VERSION 5.7 ;
  NOWIREEXTENSIONATPIN ON ;
  DIVIDERCHAR "/" ;
  BUSBITCHARS "[]" ;
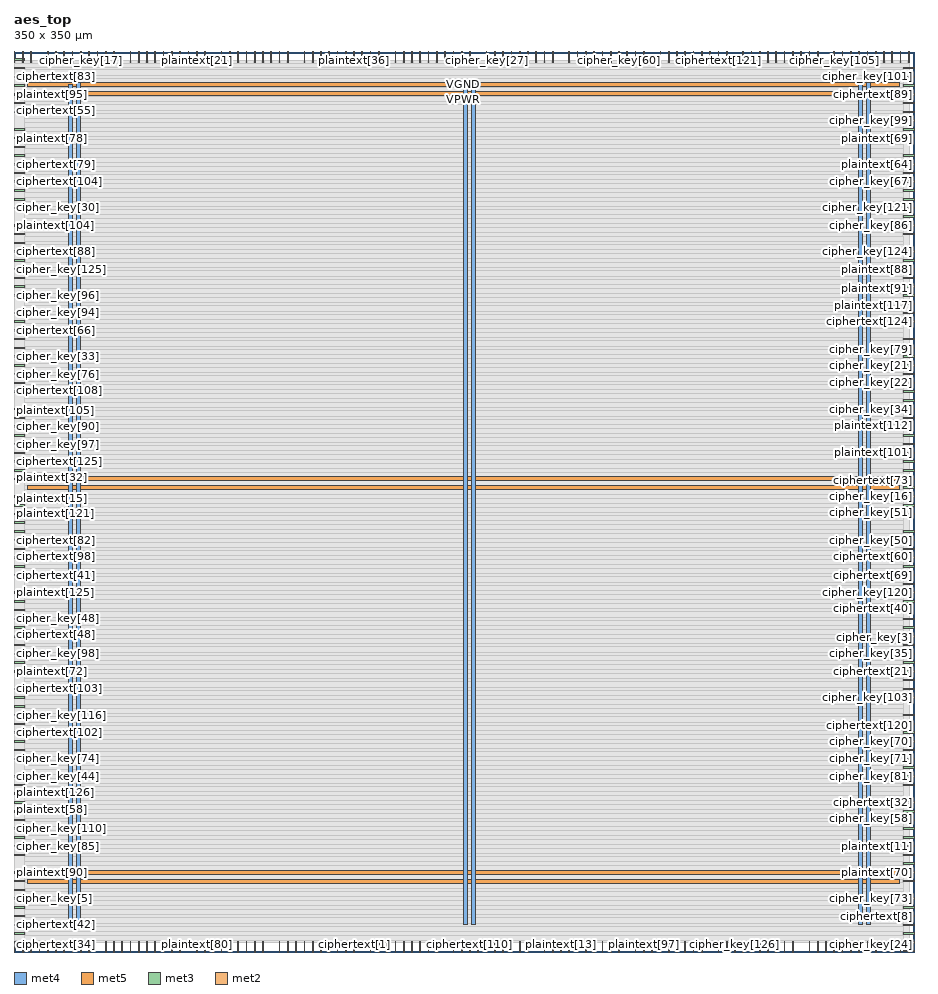
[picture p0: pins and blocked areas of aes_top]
MACRO aes_top
  CLASS BLOCK ;
  FOREIGN aes_top ;
  ORIGIN 0.000 0.000 ;
  SIZE 350.000 BY 350.000 ;
  PIN VGND
    DIRECTION INOUT ;
    USE GROUND ;
    PORT
      LAYER met4 ;
        RECT 24.340 10.640 25.940 337.990 ;
    END
    PORT
      LAYER met4 ;
        RECT 177.940 10.640 179.540 337.990 ;
    END
    PORT
      LAYER met4 ;
        RECT 331.540 10.640 333.140 337.990 ;
    END
    PORT
      LAYER met5 ;
        RECT 5.280 30.030 344.320 31.630 ;
    END
    PORT
      LAYER met5 ;
        RECT 5.280 183.210 344.320 184.810 ;
    END
    PORT
      LAYER met5 ;
        RECT 5.280 336.390 344.320 337.990 ;
    END
  END VGND
  PIN VPWR
    DIRECTION INOUT ;
    USE POWER ;
    PORT
      LAYER met4 ;
        RECT 21.040 10.640 22.640 337.520 ;
    END
    PORT
      LAYER met4 ;
        RECT 174.640 10.640 176.240 337.520 ;
    END
    PORT
      LAYER met4 ;
        RECT 328.240 10.640 329.840 337.520 ;
    END
    PORT
      LAYER met5 ;
        RECT 5.280 26.730 344.320 28.330 ;
    END
    PORT
      LAYER met5 ;
        RECT 5.280 179.910 344.320 181.510 ;
    END
    PORT
      LAYER met5 ;
        RECT 5.280 333.090 344.320 334.690 ;
    END
  END VPWR
  PIN cipher_key[0]
    DIRECTION INPUT ;
    USE SIGNAL ;
    PORT
      LAYER met3 ;
        RECT 346.000 34.040 350.000 34.640 ;
    END
  END cipher_key[0]
  PIN cipher_key[100]
    DIRECTION INPUT ;
    USE SIGNAL ;
    PORT
      LAYER met2 ;
        RECT 58.050 346.000 58.330 350.000 ;
    END
  END cipher_key[100]
  PIN cipher_key[101]
    DIRECTION INPUT ;
    USE SIGNAL ;
    PORT
      LAYER met3 ;
        RECT 346.000 340.040 350.000 340.640 ;
    END
  END cipher_key[101]
  PIN cipher_key[102]
    DIRECTION INPUT ;
    USE SIGNAL ;
    PORT
      LAYER met2 ;
        RECT 264.130 0.000 264.410 4.000 ;
    END
  END cipher_key[102]
  PIN cipher_key[103]
    DIRECTION INPUT ;
    USE SIGNAL ;
    PORT
      LAYER met3 ;
        RECT 346.000 98.640 350.000 99.240 ;
    END
  END cipher_key[103]
  PIN cipher_key[104]
    DIRECTION INPUT ;
    USE SIGNAL ;
    PORT
      LAYER met3 ;
        RECT 346.000 27.240 350.000 27.840 ;
    END
  END cipher_key[104]
  PIN cipher_key[105]
    DIRECTION INPUT ;
    USE SIGNAL ;
    PORT
      LAYER met2 ;
        RECT 318.870 346.000 319.150 350.000 ;
    END
  END cipher_key[105]
  PIN cipher_key[106]
    DIRECTION INPUT ;
    USE SIGNAL ;
    PORT
      LAYER met2 ;
        RECT 138.550 346.000 138.830 350.000 ;
    END
  END cipher_key[106]
  PIN cipher_key[107]
    DIRECTION INPUT ;
    USE SIGNAL ;
    PORT
      LAYER met3 ;
        RECT 0.000 292.440 4.000 293.040 ;
    END
  END cipher_key[107]
  PIN cipher_key[108]
    DIRECTION INPUT ;
    USE SIGNAL ;
    PORT
      LAYER met2 ;
        RECT 116.010 0.000 116.290 4.000 ;
    END
  END cipher_key[108]
  PIN cipher_key[109]
    DIRECTION INPUT ;
    USE SIGNAL ;
    PORT
      LAYER met2 ;
        RECT 241.590 346.000 241.870 350.000 ;
    END
  END cipher_key[109]
  PIN cipher_key[10]
    DIRECTION INPUT ;
    USE SIGNAL ;
    PORT
      LAYER met3 ;
        RECT 0.000 112.240 4.000 112.840 ;
    END
  END cipher_key[10]
  PIN cipher_key[110]
    DIRECTION INPUT ;
    USE SIGNAL ;
    PORT
      LAYER met3 ;
        RECT 0.000 47.640 4.000 48.240 ;
    END
  END cipher_key[110]
  PIN cipher_key[111]
    DIRECTION INPUT ;
    USE SIGNAL ;
    PORT
      LAYER met2 ;
        RECT 148.210 0.000 148.490 4.000 ;
    END
  END cipher_key[111]
  PIN cipher_key[112]
    DIRECTION INPUT ;
    USE SIGNAL ;
    PORT
      LAYER met3 ;
        RECT 0.000 88.440 4.000 89.040 ;
    END
  END cipher_key[112]
  PIN cipher_key[113]
    DIRECTION INPUT ;
    USE SIGNAL ;
    PORT
      LAYER met3 ;
        RECT 0.000 17.040 4.000 17.640 ;
    END
  END cipher_key[113]
  PIN cipher_key[114]
    DIRECTION INPUT ;
    USE SIGNAL ;
    PORT
      LAYER met3 ;
        RECT 0.000 346.840 4.000 347.440 ;
    END
  END cipher_key[114]
  PIN cipher_key[115]
    DIRECTION INPUT ;
    USE SIGNAL ;
    PORT
      LAYER met2 ;
        RECT 328.530 346.000 328.810 350.000 ;
    END
  END cipher_key[115]
  PIN cipher_key[116]
    DIRECTION INPUT ;
    USE SIGNAL ;
    PORT
      LAYER met3 ;
        RECT 0.000 91.840 4.000 92.440 ;
    END
  END cipher_key[116]
  PIN cipher_key[117]
    DIRECTION INPUT ;
    USE SIGNAL ;
    PORT
      LAYER met2 ;
        RECT 154.650 346.000 154.930 350.000 ;
    END
  END cipher_key[117]
  PIN cipher_key[118]
    DIRECTION INPUT ;
    USE SIGNAL ;
    PORT
      LAYER met3 ;
        RECT 0.000 183.640 4.000 184.240 ;
    END
  END cipher_key[118]
  PIN cipher_key[119]
    DIRECTION INPUT ;
    USE SIGNAL ;
    PORT
      LAYER met3 ;
        RECT 346.000 302.640 350.000 303.240 ;
    END
  END cipher_key[119]
  PIN cipher_key[11]
    DIRECTION INPUT ;
    USE SIGNAL ;
    PORT
      LAYER met2 ;
        RECT 148.210 346.000 148.490 350.000 ;
    END
  END cipher_key[11]
  PIN cipher_key[120]
    DIRECTION INPUT ;
    USE SIGNAL ;
    PORT
      LAYER met3 ;
        RECT 346.000 139.440 350.000 140.040 ;
    END
  END cipher_key[120]
  PIN cipher_key[121]
    DIRECTION INPUT ;
    USE SIGNAL ;
    PORT
      LAYER met3 ;
        RECT 346.000 289.040 350.000 289.640 ;
    END
  END cipher_key[121]
  PIN cipher_key[122]
    DIRECTION INPUT ;
    USE SIGNAL ;
    PORT
      LAYER met2 ;
        RECT 228.710 0.000 228.990 4.000 ;
    END
  END cipher_key[122]
  PIN cipher_key[123]
    DIRECTION INPUT ;
    USE SIGNAL ;
    PORT
      LAYER met3 ;
        RECT 346.000 71.440 350.000 72.040 ;
    END
  END cipher_key[123]
  PIN cipher_key[124]
    DIRECTION INPUT ;
    USE SIGNAL ;
    PORT
      LAYER met3 ;
        RECT 346.000 272.040 350.000 272.640 ;
    END
  END cipher_key[124]
  PIN cipher_key[125]
    DIRECTION INPUT ;
    USE SIGNAL ;
    PORT
      LAYER met3 ;
        RECT 0.000 265.240 4.000 265.840 ;
    END
  END cipher_key[125]
  PIN cipher_key[126]
    DIRECTION INPUT ;
    USE SIGNAL ;
    PORT
      LAYER met2 ;
        RECT 280.230 0.000 280.510 4.000 ;
    END
  END cipher_key[126]
  PIN cipher_key[127]
    DIRECTION INPUT ;
    USE SIGNAL ;
    PORT
      LAYER met3 ;
        RECT 0.000 261.840 4.000 262.440 ;
    END
  END cipher_key[127]
  PIN cipher_key[12]
    DIRECTION INPUT ;
    USE SIGNAL ;
    PORT
      LAYER met2 ;
        RECT 77.370 0.000 77.650 4.000 ;
    END
  END cipher_key[12]
  PIN cipher_key[13]
    DIRECTION INPUT ;
    USE SIGNAL ;
    PORT
      LAYER met2 ;
        RECT 6.530 346.000 6.810 350.000 ;
    END
  END cipher_key[13]
  PIN cipher_key[14]
    DIRECTION INPUT ;
    USE SIGNAL ;
    PORT
      LAYER met2 ;
        RECT 264.130 346.000 264.410 350.000 ;
    END
  END cipher_key[14]
  PIN cipher_key[15]
    DIRECTION INPUT ;
    USE SIGNAL ;
    PORT
      LAYER met2 ;
        RECT 328.530 0.000 328.810 4.000 ;
    END
  END cipher_key[15]
  PIN cipher_key[16]
    DIRECTION INPUT ;
    USE SIGNAL ;
    PORT
      LAYER met3 ;
        RECT 346.000 176.840 350.000 177.440 ;
    END
  END cipher_key[16]
  PIN cipher_key[17]
    DIRECTION INPUT ;
    USE SIGNAL ;
    PORT
      LAYER met2 ;
        RECT 25.850 346.000 26.130 350.000 ;
    END
  END cipher_key[17]
  PIN cipher_key[18]
    DIRECTION INPUT ;
    USE SIGNAL ;
    PORT
      LAYER met2 ;
        RECT 22.630 346.000 22.910 350.000 ;
    END
  END cipher_key[18]
  PIN cipher_key[19]
    DIRECTION INPUT ;
    USE SIGNAL ;
    PORT
      LAYER met2 ;
        RECT 289.890 346.000 290.170 350.000 ;
    END
  END cipher_key[19]
  PIN cipher_key[1]
    DIRECTION INPUT ;
    USE SIGNAL ;
    PORT
      LAYER met3 ;
        RECT 0.000 343.440 4.000 344.040 ;
    END
  END cipher_key[1]
  PIN cipher_key[20]
    DIRECTION INPUT ;
    USE SIGNAL ;
    PORT
      LAYER met3 ;
        RECT 0.000 234.640 4.000 235.240 ;
    END
  END cipher_key[20]
  PIN cipher_key[21]
    DIRECTION INPUT ;
    USE SIGNAL ;
    PORT
      LAYER met3 ;
        RECT 346.000 227.840 350.000 228.440 ;
    END
  END cipher_key[21]
  PIN cipher_key[22]
    DIRECTION INPUT ;
    USE SIGNAL ;
    PORT
      LAYER met3 ;
        RECT 346.000 221.040 350.000 221.640 ;
    END
  END cipher_key[22]
  PIN cipher_key[23]
    DIRECTION INPUT ;
    USE SIGNAL ;
    PORT
      LAYER met3 ;
        RECT 346.000 285.640 350.000 286.240 ;
    END
  END cipher_key[23]
  PIN cipher_key[24]
    DIRECTION INPUT ;
    USE SIGNAL ;
    PORT
      LAYER met2 ;
        RECT 341.410 0.000 341.690 4.000 ;
    END
  END cipher_key[24]
  PIN cipher_key[25]
    DIRECTION INPUT ;
    USE SIGNAL ;
    PORT
      LAYER met2 ;
        RECT 93.470 346.000 93.750 350.000 ;
    END
  END cipher_key[25]
  PIN cipher_key[26]
    DIRECTION INPUT ;
    USE SIGNAL ;
    PORT
      LAYER met2 ;
        RECT 141.770 0.000 142.050 4.000 ;
    END
  END cipher_key[26]
  PIN cipher_key[27]
    DIRECTION INPUT ;
    USE SIGNAL ;
    PORT
      LAYER met2 ;
        RECT 183.630 346.000 183.910 350.000 ;
    END
  END cipher_key[27]
  PIN cipher_key[28]
    DIRECTION INPUT ;
    USE SIGNAL ;
    PORT
      LAYER met3 ;
        RECT 0.000 268.640 4.000 269.240 ;
    END
  END cipher_key[28]
  PIN cipher_key[29]
    DIRECTION INPUT ;
    USE SIGNAL ;
    PORT
      LAYER met2 ;
        RECT 29.070 0.000 29.350 4.000 ;
    END
  END cipher_key[29]
  PIN cipher_key[2]
    DIRECTION INPUT ;
    USE SIGNAL ;
    PORT
      LAYER met2 ;
        RECT 241.590 0.000 241.870 4.000 ;
    END
  END cipher_key[2]
  PIN cipher_key[30]
    DIRECTION INPUT ;
    USE SIGNAL ;
    PORT
      LAYER met3 ;
        RECT 0.000 289.040 4.000 289.640 ;
    END
  END cipher_key[30]
  PIN cipher_key[31]
    DIRECTION INPUT ;
    USE SIGNAL ;
    PORT
      LAYER met2 ;
        RECT 347.850 346.000 348.130 350.000 ;
    END
  END cipher_key[31]
  PIN cipher_key[32]
    DIRECTION INPUT ;
    USE SIGNAL ;
    PORT
      LAYER met2 ;
        RECT 64.490 346.000 64.770 350.000 ;
    END
  END cipher_key[32]
  PIN cipher_key[33]
    DIRECTION INPUT ;
    USE SIGNAL ;
    PORT
      LAYER met3 ;
        RECT 0.000 231.240 4.000 231.840 ;
    END
  END cipher_key[33]
  PIN cipher_key[34]
    DIRECTION INPUT ;
    USE SIGNAL ;
    PORT
      LAYER met3 ;
        RECT 346.000 210.840 350.000 211.440 ;
    END
  END cipher_key[34]
  PIN cipher_key[35]
    DIRECTION INPUT ;
    USE SIGNAL ;
    PORT
      LAYER met3 ;
        RECT 346.000 115.640 350.000 116.240 ;
    END
  END cipher_key[35]
  PIN cipher_key[36]
    DIRECTION INPUT ;
    USE SIGNAL ;
    PORT
      LAYER met2 ;
        RECT 109.570 0.000 109.850 4.000 ;
    END
  END cipher_key[36]
  PIN cipher_key[37]
    DIRECTION INPUT ;
    USE SIGNAL ;
    PORT
      LAYER met2 ;
        RECT 222.270 0.000 222.550 4.000 ;
    END
  END cipher_key[37]
  PIN cipher_key[38]
    DIRECTION INPUT ;
    USE SIGNAL ;
    PORT
      LAYER met3 ;
        RECT 0.000 149.640 4.000 150.240 ;
    END
  END cipher_key[38]
  PIN cipher_key[39]
    DIRECTION INPUT ;
    USE SIGNAL ;
    PORT
      LAYER met2 ;
        RECT 338.190 346.000 338.470 350.000 ;
    END
  END cipher_key[39]
  PIN cipher_key[3]
    DIRECTION INPUT ;
    USE SIGNAL ;
    PORT
      LAYER met3 ;
        RECT 346.000 119.040 350.000 119.640 ;
    END
  END cipher_key[3]
  PIN cipher_key[40]
    DIRECTION INPUT ;
    USE SIGNAL ;
    PORT
      LAYER met2 ;
        RECT 296.330 0.000 296.610 4.000 ;
    END
  END cipher_key[40]
  PIN cipher_key[41]
    DIRECTION INPUT ;
    USE SIGNAL ;
    PORT
      LAYER met2 ;
        RECT 299.550 0.000 299.830 4.000 ;
    END
  END cipher_key[41]
  PIN cipher_key[42]
    DIRECTION INPUT ;
    USE SIGNAL ;
    PORT
      LAYER met3 ;
        RECT 346.000 326.440 350.000 327.040 ;
    END
  END cipher_key[42]
  PIN cipher_key[43]
    DIRECTION INPUT ;
    USE SIGNAL ;
    PORT
      LAYER met2 ;
        RECT 125.670 346.000 125.950 350.000 ;
    END
  END cipher_key[43]
  PIN cipher_key[44]
    DIRECTION INPUT ;
    USE SIGNAL ;
    PORT
      LAYER met3 ;
        RECT 0.000 68.040 4.000 68.640 ;
    END
  END cipher_key[44]
  PIN cipher_key[45]
    DIRECTION INPUT ;
    USE SIGNAL ;
    PORT
      LAYER met2 ;
        RECT 283.450 346.000 283.730 350.000 ;
    END
  END cipher_key[45]
  PIN cipher_key[46]
    DIRECTION INPUT ;
    USE SIGNAL ;
    PORT
      LAYER met3 ;
        RECT 346.000 6.840 350.000 7.440 ;
    END
  END cipher_key[46]
  PIN cipher_key[47]
    DIRECTION INPUT ;
    USE SIGNAL ;
    PORT
      LAYER met3 ;
        RECT 0.000 336.640 4.000 337.240 ;
    END
  END cipher_key[47]
  PIN cipher_key[48]
    DIRECTION INPUT ;
    USE SIGNAL ;
    PORT
      LAYER met3 ;
        RECT 0.000 129.240 4.000 129.840 ;
    END
  END cipher_key[48]
  PIN cipher_key[49]
    DIRECTION INPUT ;
    USE SIGNAL ;
    PORT
      LAYER met2 ;
        RECT 173.970 346.000 174.250 350.000 ;
    END
  END cipher_key[49]
  PIN cipher_key[4]
    DIRECTION INPUT ;
    USE SIGNAL ;
    PORT
      LAYER met3 ;
        RECT 346.000 278.840 350.000 279.440 ;
    END
  END cipher_key[4]
  PIN cipher_key[50]
    DIRECTION INPUT ;
    USE SIGNAL ;
    PORT
      LAYER met3 ;
        RECT 346.000 159.840 350.000 160.440 ;
    END
  END cipher_key[50]
  PIN cipher_key[51]
    DIRECTION INPUT ;
    USE SIGNAL ;
    PORT
      LAYER met3 ;
        RECT 346.000 173.440 350.000 174.040 ;
    END
  END cipher_key[51]
  PIN cipher_key[52]
    DIRECTION INPUT ;
    USE SIGNAL ;
    PORT
      LAYER met3 ;
        RECT 0.000 312.840 4.000 313.440 ;
    END
  END cipher_key[52]
  PIN cipher_key[53]
    DIRECTION INPUT ;
    USE SIGNAL ;
    PORT
      LAYER met3 ;
        RECT 346.000 258.440 350.000 259.040 ;
    END
  END cipher_key[53]
  PIN cipher_key[54]
    DIRECTION INPUT ;
    USE SIGNAL ;
    PORT
      LAYER met2 ;
        RECT 199.730 346.000 200.010 350.000 ;
    END
  END cipher_key[54]
  PIN cipher_key[55]
    DIRECTION INPUT ;
    USE SIGNAL ;
    PORT
      LAYER met2 ;
        RECT 87.030 346.000 87.310 350.000 ;
    END
  END cipher_key[55]
  PIN cipher_key[56]
    DIRECTION INPUT ;
    USE SIGNAL ;
    PORT
      LAYER met2 ;
        RECT 38.730 0.000 39.010 4.000 ;
    END
  END cipher_key[56]
  PIN cipher_key[57]
    DIRECTION INPUT ;
    USE SIGNAL ;
    PORT
      LAYER met2 ;
        RECT 193.290 0.000 193.570 4.000 ;
    END
  END cipher_key[57]
  PIN cipher_key[58]
    DIRECTION INPUT ;
    USE SIGNAL ;
    PORT
      LAYER met3 ;
        RECT 346.000 54.440 350.000 55.040 ;
    END
  END cipher_key[58]
  PIN cipher_key[59]
    DIRECTION INPUT ;
    USE SIGNAL ;
    PORT
      LAYER met2 ;
        RECT 74.150 346.000 74.430 350.000 ;
    END
  END cipher_key[59]
  PIN cipher_key[5]
    DIRECTION INPUT ;
    USE SIGNAL ;
    PORT
      LAYER met3 ;
        RECT 0.000 20.440 4.000 21.040 ;
    END
  END cipher_key[5]
  PIN cipher_key[60]
    DIRECTION INPUT ;
    USE SIGNAL ;
    PORT
      LAYER met2 ;
        RECT 235.150 346.000 235.430 350.000 ;
    END
  END cipher_key[60]
  PIN cipher_key[61]
    DIRECTION INPUT ;
    USE SIGNAL ;
    PORT
      LAYER met2 ;
        RECT 80.590 0.000 80.870 4.000 ;
    END
  END cipher_key[61]
  PIN cipher_key[62]
    DIRECTION INPUT ;
    USE SIGNAL ;
    PORT
      LAYER met3 ;
        RECT 0.000 132.640 4.000 133.240 ;
    END
  END cipher_key[62]
  PIN cipher_key[63]
    DIRECTION INPUT ;
    USE SIGNAL ;
    PORT
      LAYER met3 ;
        RECT 346.000 329.840 350.000 330.440 ;
    END
  END cipher_key[63]
  PIN cipher_key[64]
    DIRECTION INPUT ;
    USE SIGNAL ;
    PORT
      LAYER met2 ;
        RECT 16.190 346.000 16.470 350.000 ;
    END
  END cipher_key[64]
  PIN cipher_key[65]
    DIRECTION INPUT ;
    USE SIGNAL ;
    PORT
      LAYER met2 ;
        RECT 157.870 0.000 158.150 4.000 ;
    END
  END cipher_key[65]
  PIN cipher_key[66]
    DIRECTION INPUT ;
    USE SIGNAL ;
    PORT
      LAYER met2 ;
        RECT 312.430 0.000 312.710 4.000 ;
    END
  END cipher_key[66]
  PIN cipher_key[67]
    DIRECTION INPUT ;
    USE SIGNAL ;
    PORT
      LAYER met3 ;
        RECT 346.000 299.240 350.000 299.840 ;
    END
  END cipher_key[67]
  PIN cipher_key[68]
    DIRECTION INPUT ;
    USE SIGNAL ;
    PORT
      LAYER met3 ;
        RECT 346.000 47.640 350.000 48.240 ;
    END
  END cipher_key[68]
  PIN cipher_key[69]
    DIRECTION INPUT ;
    USE SIGNAL ;
    PORT
      LAYER met2 ;
        RECT 29.070 346.000 29.350 350.000 ;
    END
  END cipher_key[69]
  PIN cipher_key[6]
    DIRECTION INPUT ;
    USE SIGNAL ;
    PORT
      LAYER met2 ;
        RECT 331.750 0.000 332.030 4.000 ;
    END
  END cipher_key[6]
  PIN cipher_key[70]
    DIRECTION INPUT ;
    USE SIGNAL ;
    PORT
      LAYER met3 ;
        RECT 346.000 81.640 350.000 82.240 ;
    END
  END cipher_key[70]
  PIN cipher_key[71]
    DIRECTION INPUT ;
    USE SIGNAL ;
    PORT
      LAYER met3 ;
        RECT 346.000 74.840 350.000 75.440 ;
    END
  END cipher_key[71]
  PIN cipher_key[72]
    DIRECTION INPUT ;
    USE SIGNAL ;
    PORT
      LAYER met2 ;
        RECT 103.130 0.000 103.410 4.000 ;
    END
  END cipher_key[72]
  PIN cipher_key[73]
    DIRECTION INPUT ;
    USE SIGNAL ;
    PORT
      LAYER met3 ;
        RECT 346.000 20.440 350.000 21.040 ;
    END
  END cipher_key[73]
  PIN cipher_key[74]
    DIRECTION INPUT ;
    USE SIGNAL ;
    PORT
      LAYER met3 ;
        RECT 0.000 74.840 4.000 75.440 ;
    END
  END cipher_key[74]
  PIN cipher_key[75]
    DIRECTION INPUT ;
    USE SIGNAL ;
    PORT
      LAYER met3 ;
        RECT 346.000 268.640 350.000 269.240 ;
    END
  END cipher_key[75]
  PIN cipher_key[76]
    DIRECTION INPUT ;
    USE SIGNAL ;
    PORT
      LAYER met3 ;
        RECT 0.000 224.440 4.000 225.040 ;
    END
  END cipher_key[76]
  PIN cipher_key[77]
    DIRECTION INPUT ;
    USE SIGNAL ;
    PORT
      LAYER met2 ;
        RECT 87.030 0.000 87.310 4.000 ;
    END
  END cipher_key[77]
  PIN cipher_key[78]
    DIRECTION INPUT ;
    USE SIGNAL ;
    PORT
      LAYER met2 ;
        RECT 209.390 346.000 209.670 350.000 ;
    END
  END cipher_key[78]
  PIN cipher_key[79]
    DIRECTION INPUT ;
    USE SIGNAL ;
    PORT
      LAYER met3 ;
        RECT 346.000 231.240 350.000 231.840 ;
    END
  END cipher_key[79]
  PIN cipher_key[7]
    DIRECTION INPUT ;
    USE SIGNAL ;
    PORT
      LAYER met2 ;
        RECT 164.310 346.000 164.590 350.000 ;
    END
  END cipher_key[7]
  PIN cipher_key[80]
    DIRECTION INPUT ;
    USE SIGNAL ;
    PORT
      LAYER met2 ;
        RECT 19.410 0.000 19.690 4.000 ;
    END
  END cipher_key[80]
  PIN cipher_key[81]
    DIRECTION INPUT ;
    USE SIGNAL ;
    PORT
      LAYER met3 ;
        RECT 346.000 68.040 350.000 68.640 ;
    END
  END cipher_key[81]
  PIN cipher_key[82]
    DIRECTION INPUT ;
    USE SIGNAL ;
    PORT
      LAYER met2 ;
        RECT 215.830 346.000 216.110 350.000 ;
    END
  END cipher_key[82]
  PIN cipher_key[83]
    DIRECTION INPUT ;
    USE SIGNAL ;
    PORT
      LAYER met2 ;
        RECT 273.790 0.000 274.070 4.000 ;
    END
  END cipher_key[83]
  PIN cipher_key[84]
    DIRECTION INPUT ;
    USE SIGNAL ;
    PORT
      LAYER met2 ;
        RECT 215.830 0.000 216.110 4.000 ;
    END
  END cipher_key[84]
  PIN cipher_key[85]
    DIRECTION INPUT ;
    USE SIGNAL ;
    PORT
      LAYER met3 ;
        RECT 0.000 40.840 4.000 41.440 ;
    END
  END cipher_key[85]
  PIN cipher_key[86]
    DIRECTION INPUT ;
    USE SIGNAL ;
    PORT
      LAYER met3 ;
        RECT 346.000 282.240 350.000 282.840 ;
    END
  END cipher_key[86]
  PIN cipher_key[87]
    DIRECTION INPUT ;
    USE SIGNAL ;
    PORT
      LAYER met2 ;
        RECT 125.670 0.000 125.950 4.000 ;
    END
  END cipher_key[87]
  PIN cipher_key[88]
    DIRECTION INPUT ;
    USE SIGNAL ;
    PORT
      LAYER met2 ;
        RECT 64.490 0.000 64.770 4.000 ;
    END
  END cipher_key[88]
  PIN cipher_key[89]
    DIRECTION INPUT ;
    USE SIGNAL ;
    PORT
      LAYER met3 ;
        RECT 346.000 37.440 350.000 38.040 ;
    END
  END cipher_key[89]
  PIN cipher_key[8]
    DIRECTION INPUT ;
    USE SIGNAL ;
    PORT
      LAYER met2 ;
        RECT 96.690 0.000 96.970 4.000 ;
    END
  END cipher_key[8]
  PIN cipher_key[90]
    DIRECTION INPUT ;
    USE SIGNAL ;
    PORT
      LAYER met3 ;
        RECT 0.000 204.040 4.000 204.640 ;
    END
  END cipher_key[90]
  PIN cipher_key[91]
    DIRECTION INPUT ;
    USE SIGNAL ;
    PORT
      LAYER met2 ;
        RECT 3.310 346.000 3.590 350.000 ;
    END
  END cipher_key[91]
  PIN cipher_key[92]
    DIRECTION INPUT ;
    USE SIGNAL ;
    PORT
      LAYER met2 ;
        RECT 48.390 0.000 48.670 4.000 ;
    END
  END cipher_key[92]
  PIN cipher_key[93]
    DIRECTION INPUT ;
    USE SIGNAL ;
    PORT
      LAYER met2 ;
        RECT 293.110 0.000 293.390 4.000 ;
    END
  END cipher_key[93]
  PIN cipher_key[94]
    DIRECTION INPUT ;
    USE SIGNAL ;
    PORT
      LAYER met3 ;
        RECT 0.000 248.240 4.000 248.840 ;
    END
  END cipher_key[94]
  PIN cipher_key[95]
    DIRECTION INPUT ;
    USE SIGNAL ;
    PORT
      LAYER met2 ;
        RECT 209.390 0.000 209.670 4.000 ;
    END
  END cipher_key[95]
  PIN cipher_key[96]
    DIRECTION INPUT ;
    USE SIGNAL ;
    PORT
      LAYER met3 ;
        RECT 0.000 255.040 4.000 255.640 ;
    END
  END cipher_key[96]
  PIN cipher_key[97]
    DIRECTION INPUT ;
    USE SIGNAL ;
    PORT
      LAYER met3 ;
        RECT 0.000 197.240 4.000 197.840 ;
    END
  END cipher_key[97]
  PIN cipher_key[98]
    DIRECTION INPUT ;
    USE SIGNAL ;
    PORT
      LAYER met3 ;
        RECT 0.000 115.640 4.000 116.240 ;
    END
  END cipher_key[98]
  PIN cipher_key[99]
    DIRECTION INPUT ;
    USE SIGNAL ;
    PORT
      LAYER met3 ;
        RECT 346.000 323.040 350.000 323.640 ;
    END
  END cipher_key[99]
  PIN cipher_key[9]
    DIRECTION INPUT ;
    USE SIGNAL ;
    PORT
      LAYER met3 ;
        RECT 0.000 23.840 4.000 24.440 ;
    END
  END cipher_key[9]
  PIN ciphertext[0]
    DIRECTION OUTPUT TRISTATE ;
    USE SIGNAL ;
    PORT
      LAYER met2 ;
        RECT 138.550 0.000 138.830 4.000 ;
    END
  END ciphertext[0]
  PIN ciphertext[100]
    DIRECTION OUTPUT TRISTATE ;
    USE SIGNAL ;
    PORT
      LAYER met2 ;
        RECT 312.430 346.000 312.710 350.000 ;
    END
  END ciphertext[100]
  PIN ciphertext[101]
    DIRECTION OUTPUT TRISTATE ;
    USE SIGNAL ;
    PORT
      LAYER met3 ;
        RECT 346.000 214.240 350.000 214.840 ;
    END
  END ciphertext[101]
  PIN ciphertext[102]
    DIRECTION OUTPUT TRISTATE ;
    USE SIGNAL ;
    PORT
      LAYER met3 ;
        RECT 0.000 85.040 4.000 85.640 ;
    END
  END ciphertext[102]
  PIN ciphertext[103]
    DIRECTION OUTPUT TRISTATE ;
    USE SIGNAL ;
    PORT
      LAYER met3 ;
        RECT 0.000 102.040 4.000 102.640 ;
    END
  END ciphertext[103]
  PIN ciphertext[104]
    DIRECTION OUTPUT TRISTATE ;
    USE SIGNAL ;
    PORT
      LAYER met3 ;
        RECT 0.000 299.240 4.000 299.840 ;
    END
  END ciphertext[104]
  PIN ciphertext[105]
    DIRECTION OUTPUT TRISTATE ;
    USE SIGNAL ;
    PORT
      LAYER met2 ;
        RECT 309.210 0.000 309.490 4.000 ;
    END
  END ciphertext[105]
  PIN ciphertext[106]
    DIRECTION OUTPUT TRISTATE ;
    USE SIGNAL ;
    PORT
      LAYER met3 ;
        RECT 0.000 278.840 4.000 279.440 ;
    END
  END ciphertext[106]
  PIN ciphertext[107]
    DIRECTION OUTPUT TRISTATE ;
    USE SIGNAL ;
    PORT
      LAYER met2 ;
        RECT 296.330 346.000 296.610 350.000 ;
    END
  END ciphertext[107]
  PIN ciphertext[108]
    DIRECTION OUTPUT TRISTATE ;
    USE SIGNAL ;
    PORT
      LAYER met3 ;
        RECT 0.000 221.040 4.000 221.640 ;
    END
  END ciphertext[108]
  PIN ciphertext[109]
    DIRECTION OUTPUT TRISTATE ;
    USE SIGNAL ;
    PORT
      LAYER met2 ;
        RECT 35.510 346.000 35.790 350.000 ;
    END
  END ciphertext[109]
  PIN ciphertext[10]
    DIRECTION OUTPUT TRISTATE ;
    USE SIGNAL ;
    PORT
      LAYER met2 ;
        RECT 154.650 0.000 154.930 4.000 ;
    END
  END ciphertext[10]
  PIN ciphertext[110]
    DIRECTION OUTPUT TRISTATE ;
    USE SIGNAL ;
    PORT
      LAYER met2 ;
        RECT 177.190 0.000 177.470 4.000 ;
    END
  END ciphertext[110]
  PIN ciphertext[111]
    DIRECTION OUTPUT TRISTATE ;
    USE SIGNAL ;
    PORT
      LAYER met2 ;
        RECT 196.510 346.000 196.790 350.000 ;
    END
  END ciphertext[111]
  PIN ciphertext[112]
    DIRECTION OUTPUT TRISTATE ;
    USE SIGNAL ;
    PORT
      LAYER met2 ;
        RECT 219.050 346.000 219.330 350.000 ;
    END
  END ciphertext[112]
  PIN ciphertext[113]
    DIRECTION OUTPUT TRISTATE ;
    USE SIGNAL ;
    PORT
      LAYER met2 ;
        RECT 299.550 346.000 299.830 350.000 ;
    END
  END ciphertext[113]
  PIN ciphertext[114]
    DIRECTION OUTPUT TRISTATE ;
    USE SIGNAL ;
    PORT
      LAYER met3 ;
        RECT 346.000 309.440 350.000 310.040 ;
    END
  END ciphertext[114]
  PIN ciphertext[115]
    DIRECTION OUTPUT TRISTATE ;
    USE SIGNAL ;
    PORT
      LAYER met2 ;
        RECT 305.990 346.000 306.270 350.000 ;
    END
  END ciphertext[115]
  PIN ciphertext[116]
    DIRECTION OUTPUT TRISTATE ;
    USE SIGNAL ;
    PORT
      LAYER met3 ;
        RECT 346.000 112.240 350.000 112.840 ;
    END
  END ciphertext[116]
  PIN ciphertext[117]
    DIRECTION OUTPUT TRISTATE ;
    USE SIGNAL ;
    PORT
      LAYER met3 ;
        RECT 346.000 122.440 350.000 123.040 ;
    END
  END ciphertext[117]
  PIN ciphertext[118]
    DIRECTION OUTPUT TRISTATE ;
    USE SIGNAL ;
    PORT
      LAYER met2 ;
        RECT 219.050 0.000 219.330 4.000 ;
    END
  END ciphertext[118]
  PIN ciphertext[119]
    DIRECTION OUTPUT TRISTATE ;
    USE SIGNAL ;
    PORT
      LAYER met2 ;
        RECT 93.470 0.000 93.750 4.000 ;
    END
  END ciphertext[119]
  PIN ciphertext[11]
    DIRECTION OUTPUT TRISTATE ;
    USE SIGNAL ;
    PORT
      LAYER met2 ;
        RECT 112.790 0.000 113.070 4.000 ;
    END
  END ciphertext[11]
  PIN ciphertext[120]
    DIRECTION OUTPUT TRISTATE ;
    USE SIGNAL ;
    PORT
      LAYER met3 ;
        RECT 346.000 85.040 350.000 85.640 ;
    END
  END ciphertext[120]
  PIN ciphertext[121]
    DIRECTION OUTPUT TRISTATE ;
    USE SIGNAL ;
    PORT
      LAYER met2 ;
        RECT 273.790 346.000 274.070 350.000 ;
    END
  END ciphertext[121]
  PIN ciphertext[122]
    DIRECTION OUTPUT TRISTATE ;
    USE SIGNAL ;
    PORT
      LAYER met3 ;
        RECT 0.000 258.440 4.000 259.040 ;
    END
  END ciphertext[122]
  PIN ciphertext[123]
    DIRECTION OUTPUT TRISTATE ;
    USE SIGNAL ;
    PORT
      LAYER met2 ;
        RECT 54.830 0.000 55.110 4.000 ;
    END
  END ciphertext[123]
  PIN ciphertext[124]
    DIRECTION OUTPUT TRISTATE ;
    USE SIGNAL ;
    PORT
      LAYER met3 ;
        RECT 346.000 244.840 350.000 245.440 ;
    END
  END ciphertext[124]
  PIN ciphertext[125]
    DIRECTION OUTPUT TRISTATE ;
    USE SIGNAL ;
    PORT
      LAYER met3 ;
        RECT 0.000 190.440 4.000 191.040 ;
    END
  END ciphertext[125]
  PIN ciphertext[126]
    DIRECTION OUTPUT TRISTATE ;
    USE SIGNAL ;
    PORT
      LAYER met3 ;
        RECT 346.000 105.440 350.000 106.040 ;
    END
  END ciphertext[126]
  PIN ciphertext[127]
    DIRECTION OUTPUT TRISTATE ;
    USE SIGNAL ;
    PORT
      LAYER met2 ;
        RECT 251.250 346.000 251.530 350.000 ;
    END
  END ciphertext[127]
  PIN ciphertext[12]
    DIRECTION OUTPUT TRISTATE ;
    USE SIGNAL ;
    PORT
      LAYER met3 ;
        RECT 346.000 183.640 350.000 184.240 ;
    END
  END ciphertext[12]
  PIN ciphertext[13]
    DIRECTION OUTPUT TRISTATE ;
    USE SIGNAL ;
    PORT
      LAYER met2 ;
        RECT 222.270 346.000 222.550 350.000 ;
    END
  END ciphertext[13]
  PIN ciphertext[14]
    DIRECTION OUTPUT TRISTATE ;
    USE SIGNAL ;
    PORT
      LAYER met3 ;
        RECT 0.000 27.240 4.000 27.840 ;
    END
  END ciphertext[14]
  PIN ciphertext[15]
    DIRECTION OUTPUT TRISTATE ;
    USE SIGNAL ;
    PORT
      LAYER met3 ;
        RECT 346.000 51.040 350.000 51.640 ;
    END
  END ciphertext[15]
  PIN ciphertext[16]
    DIRECTION OUTPUT TRISTATE ;
    USE SIGNAL ;
    PORT
      LAYER met2 ;
        RECT 193.290 346.000 193.570 350.000 ;
    END
  END ciphertext[16]
  PIN ciphertext[17]
    DIRECTION OUTPUT TRISTATE ;
    USE SIGNAL ;
    PORT
      LAYER met2 ;
        RECT 347.850 0.000 348.130 4.000 ;
    END
  END ciphertext[17]
  PIN ciphertext[18]
    DIRECTION OUTPUT TRISTATE ;
    USE SIGNAL ;
    PORT
      LAYER met2 ;
        RECT 83.810 346.000 84.090 350.000 ;
    END
  END ciphertext[18]
  PIN ciphertext[19]
    DIRECTION OUTPUT TRISTATE ;
    USE SIGNAL ;
    PORT
      LAYER met2 ;
        RECT 12.970 346.000 13.250 350.000 ;
    END
  END ciphertext[19]
  PIN ciphertext[1]
    DIRECTION OUTPUT TRISTATE ;
    USE SIGNAL ;
    PORT
      LAYER met2 ;
        RECT 132.110 0.000 132.390 4.000 ;
    END
  END ciphertext[1]
  PIN ciphertext[20]
    DIRECTION OUTPUT TRISTATE ;
    USE SIGNAL ;
    PORT
      LAYER met2 ;
        RECT 119.230 0.000 119.510 4.000 ;
    END
  END ciphertext[20]
  PIN ciphertext[21]
    DIRECTION OUTPUT TRISTATE ;
    USE SIGNAL ;
    PORT
      LAYER met3 ;
        RECT 346.000 108.840 350.000 109.440 ;
    END
  END ciphertext[21]
  PIN ciphertext[22]
    DIRECTION OUTPUT TRISTATE ;
    USE SIGNAL ;
    PORT
      LAYER met2 ;
        RECT 119.230 346.000 119.510 350.000 ;
    END
  END ciphertext[22]
  PIN ciphertext[23]
    DIRECTION OUTPUT TRISTATE ;
    USE SIGNAL ;
    PORT
      LAYER met2 ;
        RECT 177.190 346.000 177.470 350.000 ;
    END
  END ciphertext[23]
  PIN ciphertext[24]
    DIRECTION OUTPUT TRISTATE ;
    USE SIGNAL ;
    PORT
      LAYER met3 ;
        RECT 346.000 17.040 350.000 17.640 ;
    END
  END ciphertext[24]
  PIN ciphertext[25]
    DIRECTION OUTPUT TRISTATE ;
    USE SIGNAL ;
    PORT
      LAYER met2 ;
        RECT 151.430 0.000 151.710 4.000 ;
    END
  END ciphertext[25]
  PIN ciphertext[26]
    DIRECTION OUTPUT TRISTATE ;
    USE SIGNAL ;
    PORT
      LAYER met2 ;
        RECT 309.210 346.000 309.490 350.000 ;
    END
  END ciphertext[26]
  PIN ciphertext[27]
    DIRECTION OUTPUT TRISTATE ;
    USE SIGNAL ;
    PORT
      LAYER met3 ;
        RECT 346.000 224.440 350.000 225.040 ;
    END
  END ciphertext[27]
  PIN ciphertext[28]
    DIRECTION OUTPUT TRISTATE ;
    USE SIGNAL ;
    PORT
      LAYER met2 ;
        RECT 0.090 346.000 0.370 350.000 ;
    END
  END ciphertext[28]
  PIN ciphertext[29]
    DIRECTION OUTPUT TRISTATE ;
    USE SIGNAL ;
    PORT
      LAYER met2 ;
        RECT 318.870 0.000 319.150 4.000 ;
    END
  END ciphertext[29]
  PIN ciphertext[2]
    DIRECTION OUTPUT TRISTATE ;
    USE SIGNAL ;
    PORT
      LAYER met3 ;
        RECT 346.000 343.440 350.000 344.040 ;
    END
  END ciphertext[2]
  PIN ciphertext[30]
    DIRECTION OUTPUT TRISTATE ;
    USE SIGNAL ;
    PORT
      LAYER met2 ;
        RECT 196.510 0.000 196.790 4.000 ;
    END
  END ciphertext[30]
  PIN ciphertext[31]
    DIRECTION OUTPUT TRISTATE ;
    USE SIGNAL ;
    PORT
      LAYER met2 ;
        RECT 90.250 346.000 90.530 350.000 ;
    END
  END ciphertext[31]
  PIN ciphertext[32]
    DIRECTION OUTPUT TRISTATE ;
    USE SIGNAL ;
    PORT
      LAYER met3 ;
        RECT 346.000 57.840 350.000 58.440 ;
    END
  END ciphertext[32]
  PIN ciphertext[33]
    DIRECTION OUTPUT TRISTATE ;
    USE SIGNAL ;
    PORT
      LAYER met3 ;
        RECT 346.000 238.040 350.000 238.640 ;
    END
  END ciphertext[33]
  PIN ciphertext[34]
    DIRECTION OUTPUT TRISTATE ;
    USE SIGNAL ;
    PORT
      LAYER met2 ;
        RECT 16.190 0.000 16.470 4.000 ;
    END
  END ciphertext[34]
  PIN ciphertext[35]
    DIRECTION OUTPUT TRISTATE ;
    USE SIGNAL ;
    PORT
      LAYER met3 ;
        RECT 0.000 302.640 4.000 303.240 ;
    END
  END ciphertext[35]
  PIN ciphertext[36]
    DIRECTION OUTPUT TRISTATE ;
    USE SIGNAL ;
    PORT
      LAYER met2 ;
        RECT 167.530 346.000 167.810 350.000 ;
    END
  END ciphertext[36]
  PIN ciphertext[37]
    DIRECTION OUTPUT TRISTATE ;
    USE SIGNAL ;
    PORT
      LAYER met2 ;
        RECT 289.890 0.000 290.170 4.000 ;
    END
  END ciphertext[37]
  PIN ciphertext[38]
    DIRECTION OUTPUT TRISTATE ;
    USE SIGNAL ;
    PORT
      LAYER met3 ;
        RECT 0.000 275.440 4.000 276.040 ;
    END
  END ciphertext[38]
  PIN ciphertext[39]
    DIRECTION OUTPUT TRISTATE ;
    USE SIGNAL ;
    PORT
      LAYER met2 ;
        RECT 32.290 346.000 32.570 350.000 ;
    END
  END ciphertext[39]
  PIN ciphertext[3]
    DIRECTION OUTPUT TRISTATE ;
    USE SIGNAL ;
    PORT
      LAYER met2 ;
        RECT 225.490 346.000 225.770 350.000 ;
    END
  END ciphertext[3]
  PIN ciphertext[40]
    DIRECTION OUTPUT TRISTATE ;
    USE SIGNAL ;
    PORT
      LAYER met3 ;
        RECT 346.000 136.040 350.000 136.640 ;
    END
  END ciphertext[40]
  PIN ciphertext[41]
    DIRECTION OUTPUT TRISTATE ;
    USE SIGNAL ;
    PORT
      LAYER met3 ;
        RECT 0.000 146.240 4.000 146.840 ;
    END
  END ciphertext[41]
  PIN ciphertext[42]
    DIRECTION OUTPUT TRISTATE ;
    USE SIGNAL ;
    PORT
      LAYER met3 ;
        RECT 0.000 10.240 4.000 10.840 ;
    END
  END ciphertext[42]
  PIN ciphertext[43]
    DIRECTION OUTPUT TRISTATE ;
    USE SIGNAL ;
    PORT
      LAYER met2 ;
        RECT 161.090 346.000 161.370 350.000 ;
    END
  END ciphertext[43]
  PIN ciphertext[44]
    DIRECTION OUTPUT TRISTATE ;
    USE SIGNAL ;
    PORT
      LAYER met2 ;
        RECT 173.970 0.000 174.250 4.000 ;
    END
  END ciphertext[44]
  PIN ciphertext[45]
    DIRECTION OUTPUT TRISTATE ;
    USE SIGNAL ;
    PORT
      LAYER met2 ;
        RECT 116.010 346.000 116.290 350.000 ;
    END
  END ciphertext[45]
  PIN ciphertext[46]
    DIRECTION OUTPUT TRISTATE ;
    USE SIGNAL ;
    PORT
      LAYER met2 ;
        RECT 161.090 0.000 161.370 4.000 ;
    END
  END ciphertext[46]
  PIN ciphertext[47]
    DIRECTION OUTPUT TRISTATE ;
    USE SIGNAL ;
    PORT
      LAYER met3 ;
        RECT 346.000 44.240 350.000 44.840 ;
    END
  END ciphertext[47]
  PIN ciphertext[48]
    DIRECTION OUTPUT TRISTATE ;
    USE SIGNAL ;
    PORT
      LAYER met3 ;
        RECT 0.000 125.840 4.000 126.440 ;
    END
  END ciphertext[48]
  PIN ciphertext[49]
    DIRECTION OUTPUT TRISTATE ;
    USE SIGNAL ;
    PORT
      LAYER met3 ;
        RECT 0.000 217.640 4.000 218.240 ;
    END
  END ciphertext[49]
  PIN ciphertext[4]
    DIRECTION OUTPUT TRISTATE ;
    USE SIGNAL ;
    PORT
      LAYER met2 ;
        RECT 202.950 346.000 203.230 350.000 ;
    END
  END ciphertext[4]
  PIN ciphertext[50]
    DIRECTION OUTPUT TRISTATE ;
    USE SIGNAL ;
    PORT
      LAYER met3 ;
        RECT 0.000 54.440 4.000 55.040 ;
    END
  END ciphertext[50]
  PIN ciphertext[51]
    DIRECTION OUTPUT TRISTATE ;
    USE SIGNAL ;
    PORT
      LAYER met2 ;
        RECT 331.750 346.000 332.030 350.000 ;
    END
  END ciphertext[51]
  PIN ciphertext[52]
    DIRECTION OUTPUT TRISTATE ;
    USE SIGNAL ;
    PORT
      LAYER met2 ;
        RECT 67.710 346.000 67.990 350.000 ;
    END
  END ciphertext[52]
  PIN ciphertext[53]
    DIRECTION OUTPUT TRISTATE ;
    USE SIGNAL ;
    PORT
      LAYER met3 ;
        RECT 0.000 95.240 4.000 95.840 ;
    END
  END ciphertext[53]
  PIN ciphertext[54]
    DIRECTION OUTPUT TRISTATE ;
    USE SIGNAL ;
    PORT
      LAYER met2 ;
        RECT 344.630 0.000 344.910 4.000 ;
    END
  END ciphertext[54]
  PIN ciphertext[55]
    DIRECTION OUTPUT TRISTATE ;
    USE SIGNAL ;
    PORT
      LAYER met3 ;
        RECT 0.000 329.840 4.000 330.440 ;
    END
  END ciphertext[55]
  PIN ciphertext[56]
    DIRECTION OUTPUT TRISTATE ;
    USE SIGNAL ;
    PORT
      LAYER met2 ;
        RECT 206.170 346.000 206.450 350.000 ;
    END
  END ciphertext[56]
  PIN ciphertext[57]
    DIRECTION OUTPUT TRISTATE ;
    USE SIGNAL ;
    PORT
      LAYER met2 ;
        RECT 199.730 0.000 200.010 4.000 ;
    END
  END ciphertext[57]
  PIN ciphertext[58]
    DIRECTION OUTPUT TRISTATE ;
    USE SIGNAL ;
    PORT
      LAYER met3 ;
        RECT 346.000 125.840 350.000 126.440 ;
    END
  END ciphertext[58]
  PIN ciphertext[59]
    DIRECTION OUTPUT TRISTATE ;
    USE SIGNAL ;
    PORT
      LAYER met3 ;
        RECT 346.000 91.840 350.000 92.440 ;
    END
  END ciphertext[59]
  PIN ciphertext[5]
    DIRECTION OUTPUT TRISTATE ;
    USE SIGNAL ;
    PORT
      LAYER met2 ;
        RECT 128.890 346.000 129.170 350.000 ;
    END
  END ciphertext[5]
  PIN ciphertext[60]
    DIRECTION OUTPUT TRISTATE ;
    USE SIGNAL ;
    PORT
      LAYER met3 ;
        RECT 346.000 156.440 350.000 157.040 ;
    END
  END ciphertext[60]
  PIN ciphertext[61]
    DIRECTION OUTPUT TRISTATE ;
    USE SIGNAL ;
    PORT
      LAYER met2 ;
        RECT 61.270 346.000 61.550 350.000 ;
    END
  END ciphertext[61]
  PIN ciphertext[62]
    DIRECTION OUTPUT TRISTATE ;
    USE SIGNAL ;
    PORT
      LAYER met3 ;
        RECT 0.000 3.440 4.000 4.040 ;
    END
  END ciphertext[62]
  PIN ciphertext[63]
    DIRECTION OUTPUT TRISTATE ;
    USE SIGNAL ;
    PORT
      LAYER met2 ;
        RECT 235.150 0.000 235.430 4.000 ;
    END
  END ciphertext[63]
  PIN ciphertext[64]
    DIRECTION OUTPUT TRISTATE ;
    USE SIGNAL ;
    PORT
      LAYER met2 ;
        RECT 283.450 0.000 283.730 4.000 ;
    END
  END ciphertext[64]
  PIN ciphertext[65]
    DIRECTION OUTPUT TRISTATE ;
    USE SIGNAL ;
    PORT
      LAYER met2 ;
        RECT 45.170 0.000 45.450 4.000 ;
    END
  END ciphertext[65]
  PIN ciphertext[66]
    DIRECTION OUTPUT TRISTATE ;
    USE SIGNAL ;
    PORT
      LAYER met3 ;
        RECT 0.000 241.440 4.000 242.040 ;
    END
  END ciphertext[66]
  PIN ciphertext[67]
    DIRECTION OUTPUT TRISTATE ;
    USE SIGNAL ;
    PORT
      LAYER met2 ;
        RECT 254.470 0.000 254.750 4.000 ;
    END
  END ciphertext[67]
  PIN ciphertext[68]
    DIRECTION OUTPUT TRISTATE ;
    USE SIGNAL ;
    PORT
      LAYER met3 ;
        RECT 0.000 166.640 4.000 167.240 ;
    END
  END ciphertext[68]
  PIN ciphertext[69]
    DIRECTION OUTPUT TRISTATE ;
    USE SIGNAL ;
    PORT
      LAYER met3 ;
        RECT 346.000 146.240 350.000 146.840 ;
    END
  END ciphertext[69]
  PIN ciphertext[6]
    DIRECTION OUTPUT TRISTATE ;
    USE SIGNAL ;
    PORT
      LAYER met3 ;
        RECT 346.000 336.640 350.000 337.240 ;
    END
  END ciphertext[6]
  PIN ciphertext[70]
    DIRECTION OUTPUT TRISTATE ;
    USE SIGNAL ;
    PORT
      LAYER met2 ;
        RECT 344.630 346.000 344.910 350.000 ;
    END
  END ciphertext[70]
  PIN ciphertext[71]
    DIRECTION OUTPUT TRISTATE ;
    USE SIGNAL ;
    PORT
      LAYER met3 ;
        RECT 0.000 193.840 4.000 194.440 ;
    END
  END ciphertext[71]
  PIN ciphertext[72]
    DIRECTION OUTPUT TRISTATE ;
    USE SIGNAL ;
    PORT
      LAYER met2 ;
        RECT 90.250 0.000 90.530 4.000 ;
    END
  END ciphertext[72]
  PIN ciphertext[73]
    DIRECTION OUTPUT TRISTATE ;
    USE SIGNAL ;
    PORT
      LAYER met3 ;
        RECT 346.000 180.240 350.000 180.840 ;
    END
  END ciphertext[73]
  PIN ciphertext[74]
    DIRECTION OUTPUT TRISTATE ;
    USE SIGNAL ;
    PORT
      LAYER met2 ;
        RECT 286.670 0.000 286.950 4.000 ;
    END
  END ciphertext[74]
  PIN ciphertext[75]
    DIRECTION OUTPUT TRISTATE ;
    USE SIGNAL ;
    PORT
      LAYER met2 ;
        RECT 277.010 346.000 277.290 350.000 ;
    END
  END ciphertext[75]
  PIN ciphertext[76]
    DIRECTION OUTPUT TRISTATE ;
    USE SIGNAL ;
    PORT
      LAYER met2 ;
        RECT 58.050 0.000 58.330 4.000 ;
    END
  END ciphertext[76]
  PIN ciphertext[77]
    DIRECTION OUTPUT TRISTATE ;
    USE SIGNAL ;
    PORT
      LAYER met3 ;
        RECT 346.000 149.640 350.000 150.240 ;
    END
  END ciphertext[77]
  PIN ciphertext[78]
    DIRECTION OUTPUT TRISTATE ;
    USE SIGNAL ;
    PORT
      LAYER met3 ;
        RECT 346.000 295.840 350.000 296.440 ;
    END
  END ciphertext[78]
  PIN ciphertext[79]
    DIRECTION OUTPUT TRISTATE ;
    USE SIGNAL ;
    PORT
      LAYER met3 ;
        RECT 0.000 306.040 4.000 306.640 ;
    END
  END ciphertext[79]
  PIN ciphertext[7]
    DIRECTION OUTPUT TRISTATE ;
    USE SIGNAL ;
    PORT
      LAYER met3 ;
        RECT 0.000 51.040 4.000 51.640 ;
    END
  END ciphertext[7]
  PIN ciphertext[80]
    DIRECTION OUTPUT TRISTATE ;
    USE SIGNAL ;
    PORT
      LAYER met3 ;
        RECT 0.000 37.440 4.000 38.040 ;
    END
  END ciphertext[80]
  PIN ciphertext[81]
    DIRECTION OUTPUT TRISTATE ;
    USE SIGNAL ;
    PORT
      LAYER met3 ;
        RECT 346.000 251.640 350.000 252.240 ;
    END
  END ciphertext[81]
  PIN ciphertext[82]
    DIRECTION OUTPUT TRISTATE ;
    USE SIGNAL ;
    PORT
      LAYER met3 ;
        RECT 0.000 159.840 4.000 160.440 ;
    END
  END ciphertext[82]
  PIN ciphertext[83]
    DIRECTION OUTPUT TRISTATE ;
    USE SIGNAL ;
    PORT
      LAYER met3 ;
        RECT 0.000 340.040 4.000 340.640 ;
    END
  END ciphertext[83]
  PIN ciphertext[84]
    DIRECTION OUTPUT TRISTATE ;
    USE SIGNAL ;
    PORT
      LAYER met2 ;
        RECT 157.870 346.000 158.150 350.000 ;
    END
  END ciphertext[84]
  PIN ciphertext[85]
    DIRECTION OUTPUT TRISTATE ;
    USE SIGNAL ;
    PORT
      LAYER met2 ;
        RECT 3.310 0.000 3.590 4.000 ;
    END
  END ciphertext[85]
  PIN ciphertext[86]
    DIRECTION OUTPUT TRISTATE ;
    USE SIGNAL ;
    PORT
      LAYER met2 ;
        RECT 248.030 0.000 248.310 4.000 ;
    END
  END ciphertext[86]
  PIN ciphertext[87]
    DIRECTION OUTPUT TRISTATE ;
    USE SIGNAL ;
    PORT
      LAYER met2 ;
        RECT 170.750 0.000 171.030 4.000 ;
    END
  END ciphertext[87]
  PIN ciphertext[88]
    DIRECTION OUTPUT TRISTATE ;
    USE SIGNAL ;
    PORT
      LAYER met3 ;
        RECT 0.000 272.040 4.000 272.640 ;
    END
  END ciphertext[88]
  PIN ciphertext[89]
    DIRECTION OUTPUT TRISTATE ;
    USE SIGNAL ;
    PORT
      LAYER met3 ;
        RECT 346.000 333.240 350.000 333.840 ;
    END
  END ciphertext[89]
  PIN ciphertext[8]
    DIRECTION OUTPUT TRISTATE ;
    USE SIGNAL ;
    PORT
      LAYER met3 ;
        RECT 346.000 13.640 350.000 14.240 ;
    END
  END ciphertext[8]
  PIN ciphertext[90]
    DIRECTION OUTPUT TRISTATE ;
    USE SIGNAL ;
    PORT
      LAYER met2 ;
        RECT 170.750 346.000 171.030 350.000 ;
    END
  END ciphertext[90]
  PIN ciphertext[91]
    DIRECTION OUTPUT TRISTATE ;
    USE SIGNAL ;
    PORT
      LAYER met2 ;
        RECT 9.750 0.000 10.030 4.000 ;
    END
  END ciphertext[91]
  PIN ciphertext[92]
    DIRECTION OUTPUT TRISTATE ;
    USE SIGNAL ;
    PORT
      LAYER met2 ;
        RECT 61.270 0.000 61.550 4.000 ;
    END
  END ciphertext[92]
  PIN ciphertext[93]
    DIRECTION OUTPUT TRISTATE ;
    USE SIGNAL ;
    PORT
      LAYER met2 ;
        RECT 144.990 0.000 145.270 4.000 ;
    END
  END ciphertext[93]
  PIN ciphertext[94]
    DIRECTION OUTPUT TRISTATE ;
    USE SIGNAL ;
    PORT
      LAYER met2 ;
        RECT 322.090 346.000 322.370 350.000 ;
    END
  END ciphertext[94]
  PIN ciphertext[95]
    DIRECTION OUTPUT TRISTATE ;
    USE SIGNAL ;
    PORT
      LAYER met2 ;
        RECT 260.910 0.000 261.190 4.000 ;
    END
  END ciphertext[95]
  PIN ciphertext[96]
    DIRECTION OUTPUT TRISTATE ;
    USE SIGNAL ;
    PORT
      LAYER met2 ;
        RECT 122.450 0.000 122.730 4.000 ;
    END
  END ciphertext[96]
  PIN ciphertext[97]
    DIRECTION OUTPUT TRISTATE ;
    USE SIGNAL ;
    PORT
      LAYER met3 ;
        RECT 0.000 13.640 4.000 14.240 ;
    END
  END ciphertext[97]
  PIN ciphertext[98]
    DIRECTION OUTPUT TRISTATE ;
    USE SIGNAL ;
    PORT
      LAYER met3 ;
        RECT 0.000 156.440 4.000 157.040 ;
    END
  END ciphertext[98]
  PIN ciphertext[99]
    DIRECTION OUTPUT TRISTATE ;
    USE SIGNAL ;
    PORT
      LAYER met3 ;
        RECT 0.000 326.440 4.000 327.040 ;
    END
  END ciphertext[99]
  PIN ciphertext[9]
    DIRECTION OUTPUT TRISTATE ;
    USE SIGNAL ;
    PORT
      LAYER met2 ;
        RECT 103.130 346.000 103.410 350.000 ;
    END
  END ciphertext[9]
  PIN plaintext[0]
    DIRECTION INPUT ;
    USE SIGNAL ;
    PORT
      LAYER met2 ;
        RECT 48.390 346.000 48.670 350.000 ;
    END
  END plaintext[0]
  PIN plaintext[100]
    DIRECTION INPUT ;
    USE SIGNAL ;
    PORT
      LAYER met2 ;
        RECT 325.310 0.000 325.590 4.000 ;
    END
  END plaintext[100]
  PIN plaintext[101]
    DIRECTION INPUT ;
    USE SIGNAL ;
    PORT
      LAYER met3 ;
        RECT 346.000 193.840 350.000 194.440 ;
    END
  END plaintext[101]
  PIN plaintext[102]
    DIRECTION INPUT ;
    USE SIGNAL ;
    PORT
      LAYER met2 ;
        RECT 267.350 346.000 267.630 350.000 ;
    END
  END plaintext[102]
  PIN plaintext[103]
    DIRECTION INPUT ;
    USE SIGNAL ;
    PORT
      LAYER met2 ;
        RECT 80.590 346.000 80.870 350.000 ;
    END
  END plaintext[103]
  PIN plaintext[104]
    DIRECTION INPUT ;
    USE SIGNAL ;
    PORT
      LAYER met3 ;
        RECT 0.000 282.240 4.000 282.840 ;
    END
  END plaintext[104]
  PIN plaintext[105]
    DIRECTION INPUT ;
    USE SIGNAL ;
    PORT
      LAYER met3 ;
        RECT 0.000 207.440 4.000 208.040 ;
    END
  END plaintext[105]
  PIN plaintext[106]
    DIRECTION INPUT ;
    USE SIGNAL ;
    PORT
      LAYER met3 ;
        RECT 346.000 10.240 350.000 10.840 ;
    END
  END plaintext[106]
  PIN plaintext[107]
    DIRECTION INPUT ;
    USE SIGNAL ;
    PORT
      LAYER met2 ;
        RECT 238.370 346.000 238.650 350.000 ;
    END
  END plaintext[107]
  PIN plaintext[108]
    DIRECTION INPUT ;
    USE SIGNAL ;
    PORT
      LAYER met2 ;
        RECT 302.770 0.000 303.050 4.000 ;
    END
  END plaintext[108]
  PIN plaintext[109]
    DIRECTION INPUT ;
    USE SIGNAL ;
    PORT
      LAYER met2 ;
        RECT 51.610 346.000 51.890 350.000 ;
    END
  END plaintext[109]
  PIN plaintext[10]
    DIRECTION INPUT ;
    USE SIGNAL ;
    PORT
      LAYER met2 ;
        RECT 41.950 0.000 42.230 4.000 ;
    END
  END plaintext[10]
  PIN plaintext[110]
    DIRECTION INPUT ;
    USE SIGNAL ;
    PORT
      LAYER met3 ;
        RECT 346.000 153.040 350.000 153.640 ;
    END
  END plaintext[110]
  PIN plaintext[111]
    DIRECTION INPUT ;
    USE SIGNAL ;
    PORT
      LAYER met2 ;
        RECT 19.410 346.000 19.690 350.000 ;
    END
  END plaintext[111]
  PIN plaintext[112]
    DIRECTION INPUT ;
    USE SIGNAL ;
    PORT
      LAYER met3 ;
        RECT 346.000 207.440 350.000 208.040 ;
    END
  END plaintext[112]
  PIN plaintext[113]
    DIRECTION INPUT ;
    USE SIGNAL ;
    PORT
      LAYER met2 ;
        RECT 83.810 0.000 84.090 4.000 ;
    END
  END plaintext[113]
  PIN plaintext[114]
    DIRECTION INPUT ;
    USE SIGNAL ;
    PORT
      LAYER met2 ;
        RECT 315.650 0.000 315.930 4.000 ;
    END
  END plaintext[114]
  PIN plaintext[115]
    DIRECTION INPUT ;
    USE SIGNAL ;
    PORT
      LAYER met2 ;
        RECT 135.330 346.000 135.610 350.000 ;
    END
  END plaintext[115]
  PIN plaintext[116]
    DIRECTION INPUT ;
    USE SIGNAL ;
    PORT
      LAYER met2 ;
        RECT 325.310 346.000 325.590 350.000 ;
    END
  END plaintext[116]
  PIN plaintext[117]
    DIRECTION INPUT ;
    USE SIGNAL ;
    PORT
      LAYER met3 ;
        RECT 346.000 248.240 350.000 248.840 ;
    END
  END plaintext[117]
  PIN plaintext[118]
    DIRECTION INPUT ;
    USE SIGNAL ;
    PORT
      LAYER met2 ;
        RECT 122.450 346.000 122.730 350.000 ;
    END
  END plaintext[118]
  PIN plaintext[119]
    DIRECTION INPUT ;
    USE SIGNAL ;
    PORT
      LAYER met2 ;
        RECT 151.430 346.000 151.710 350.000 ;
    END
  END plaintext[119]
  PIN plaintext[11]
    DIRECTION INPUT ;
    USE SIGNAL ;
    PORT
      LAYER met3 ;
        RECT 346.000 40.840 350.000 41.440 ;
    END
  END plaintext[11]
  PIN plaintext[120]
    DIRECTION INPUT ;
    USE SIGNAL ;
    PORT
      LAYER met2 ;
        RECT 96.690 346.000 96.970 350.000 ;
    END
  END plaintext[120]
  PIN plaintext[121]
    DIRECTION INPUT ;
    USE SIGNAL ;
    PORT
      LAYER met3 ;
        RECT 0.000 170.040 4.000 170.640 ;
    END
  END plaintext[121]
  PIN plaintext[122]
    DIRECTION INPUT ;
    USE SIGNAL ;
    PORT
      LAYER met2 ;
        RECT 257.690 346.000 257.970 350.000 ;
    END
  END plaintext[122]
  PIN plaintext[123]
    DIRECTION INPUT ;
    USE SIGNAL ;
    PORT
      LAYER met2 ;
        RECT 186.850 346.000 187.130 350.000 ;
    END
  END plaintext[123]
  PIN plaintext[124]
    DIRECTION INPUT ;
    USE SIGNAL ;
    PORT
      LAYER met2 ;
        RECT 54.830 346.000 55.110 350.000 ;
    END
  END plaintext[124]
  PIN plaintext[125]
    DIRECTION INPUT ;
    USE SIGNAL ;
    PORT
      LAYER met3 ;
        RECT 0.000 139.440 4.000 140.040 ;
    END
  END plaintext[125]
  PIN plaintext[126]
    DIRECTION INPUT ;
    USE SIGNAL ;
    PORT
      LAYER met3 ;
        RECT 0.000 64.640 4.000 65.240 ;
    END
  END plaintext[126]
  PIN plaintext[127]
    DIRECTION INPUT ;
    USE SIGNAL ;
    PORT
      LAYER met3 ;
        RECT 346.000 234.640 350.000 235.240 ;
    END
  END plaintext[127]
  PIN plaintext[12]
    DIRECTION INPUT ;
    USE SIGNAL ;
    PORT
      LAYER met3 ;
        RECT 346.000 217.640 350.000 218.240 ;
    END
  END plaintext[12]
  PIN plaintext[13]
    DIRECTION INPUT ;
    USE SIGNAL ;
    PORT
      LAYER met2 ;
        RECT 212.610 0.000 212.890 4.000 ;
    END
  END plaintext[13]
  PIN plaintext[14]
    DIRECTION INPUT ;
    USE SIGNAL ;
    PORT
      LAYER met3 ;
        RECT 0.000 136.040 4.000 136.640 ;
    END
  END plaintext[14]
  PIN plaintext[15]
    DIRECTION INPUT ;
    USE SIGNAL ;
    PORT
      LAYER met3 ;
        RECT 0.000 173.440 4.000 174.040 ;
    END
  END plaintext[15]
  PIN plaintext[16]
    DIRECTION INPUT ;
    USE SIGNAL ;
    PORT
      LAYER met2 ;
        RECT 322.090 0.000 322.370 4.000 ;
    END
  END plaintext[16]
  PIN plaintext[17]
    DIRECTION INPUT ;
    USE SIGNAL ;
    PORT
      LAYER met3 ;
        RECT 0.000 61.240 4.000 61.840 ;
    END
  END plaintext[17]
  PIN plaintext[18]
    DIRECTION INPUT ;
    USE SIGNAL ;
    PORT
      LAYER met3 ;
        RECT 0.000 210.840 4.000 211.440 ;
    END
  END plaintext[18]
  PIN plaintext[19]
    DIRECTION INPUT ;
    USE SIGNAL ;
    PORT
      LAYER met2 ;
        RECT 186.850 0.000 187.130 4.000 ;
    END
  END plaintext[19]
  PIN plaintext[1]
    DIRECTION INPUT ;
    USE SIGNAL ;
    PORT
      LAYER met3 ;
        RECT 0.000 98.640 4.000 99.240 ;
    END
  END plaintext[1]
  PIN plaintext[20]
    DIRECTION INPUT ;
    USE SIGNAL ;
    PORT
      LAYER met3 ;
        RECT 346.000 64.640 350.000 65.240 ;
    END
  END plaintext[20]
  PIN plaintext[21]
    DIRECTION INPUT ;
    USE SIGNAL ;
    PORT
      LAYER met2 ;
        RECT 70.930 346.000 71.210 350.000 ;
    END
  END plaintext[21]
  PIN plaintext[22]
    DIRECTION INPUT ;
    USE SIGNAL ;
    PORT
      LAYER met2 ;
        RECT 180.410 0.000 180.690 4.000 ;
    END
  END plaintext[22]
  PIN plaintext[23]
    DIRECTION INPUT ;
    USE SIGNAL ;
    PORT
      LAYER met2 ;
        RECT 35.510 0.000 35.790 4.000 ;
    END
  END plaintext[23]
  PIN plaintext[24]
    DIRECTION INPUT ;
    USE SIGNAL ;
    PORT
      LAYER met2 ;
        RECT 141.770 346.000 142.050 350.000 ;
    END
  END plaintext[24]
  PIN plaintext[25]
    DIRECTION INPUT ;
    USE SIGNAL ;
    PORT
      LAYER met3 ;
        RECT 346.000 187.040 350.000 187.640 ;
    END
  END plaintext[25]
  PIN plaintext[26]
    DIRECTION INPUT ;
    USE SIGNAL ;
    PORT
      LAYER met3 ;
        RECT 346.000 319.640 350.000 320.240 ;
    END
  END plaintext[26]
  PIN plaintext[27]
    DIRECTION INPUT ;
    USE SIGNAL ;
    PORT
      LAYER met3 ;
        RECT 0.000 44.240 4.000 44.840 ;
    END
  END plaintext[27]
  PIN plaintext[28]
    DIRECTION INPUT ;
    USE SIGNAL ;
    PORT
      LAYER met2 ;
        RECT 293.110 346.000 293.390 350.000 ;
    END
  END plaintext[28]
  PIN plaintext[29]
    DIRECTION INPUT ;
    USE SIGNAL ;
    PORT
      LAYER met3 ;
        RECT 346.000 129.240 350.000 129.840 ;
    END
  END plaintext[29]
  PIN plaintext[2]
    DIRECTION INPUT ;
    USE SIGNAL ;
    PORT
      LAYER met2 ;
        RECT 257.690 0.000 257.970 4.000 ;
    END
  END plaintext[2]
  PIN plaintext[30]
    DIRECTION INPUT ;
    USE SIGNAL ;
    PORT
      LAYER met3 ;
        RECT 0.000 153.040 4.000 153.640 ;
    END
  END plaintext[30]
  PIN plaintext[31]
    DIRECTION INPUT ;
    USE SIGNAL ;
    PORT
      LAYER met2 ;
        RECT 251.250 0.000 251.530 4.000 ;
    END
  END plaintext[31]
  PIN plaintext[32]
    DIRECTION INPUT ;
    USE SIGNAL ;
    PORT
      LAYER met3 ;
        RECT 0.000 187.040 4.000 187.640 ;
    END
  END plaintext[32]
  PIN plaintext[33]
    DIRECTION INPUT ;
    USE SIGNAL ;
    PORT
      LAYER met3 ;
        RECT 0.000 244.840 4.000 245.440 ;
    END
  END plaintext[33]
  PIN plaintext[34]
    DIRECTION INPUT ;
    USE SIGNAL ;
    PORT
      LAYER met2 ;
        RECT 334.970 0.000 335.250 4.000 ;
    END
  END plaintext[34]
  PIN plaintext[35]
    DIRECTION INPUT ;
    USE SIGNAL ;
    PORT
      LAYER met3 ;
        RECT 346.000 78.240 350.000 78.840 ;
    END
  END plaintext[35]
  PIN plaintext[36]
    DIRECTION INPUT ;
    USE SIGNAL ;
    PORT
      LAYER met2 ;
        RECT 132.110 346.000 132.390 350.000 ;
    END
  END plaintext[36]
  PIN plaintext[37]
    DIRECTION INPUT ;
    USE SIGNAL ;
    PORT
      LAYER met3 ;
        RECT 346.000 292.440 350.000 293.040 ;
    END
  END plaintext[37]
  PIN plaintext[38]
    DIRECTION INPUT ;
    USE SIGNAL ;
    PORT
      LAYER met3 ;
        RECT 0.000 6.840 4.000 7.440 ;
    END
  END plaintext[38]
  PIN plaintext[39]
    DIRECTION INPUT ;
    USE SIGNAL ;
    PORT
      LAYER met3 ;
        RECT 0.000 319.640 4.000 320.240 ;
    END
  END plaintext[39]
  PIN plaintext[3]
    DIRECTION INPUT ;
    USE SIGNAL ;
    PORT
      LAYER met3 ;
        RECT 0.000 309.440 4.000 310.040 ;
    END
  END plaintext[3]
  PIN plaintext[40]
    DIRECTION INPUT ;
    USE SIGNAL ;
    PORT
      LAYER met2 ;
        RECT 12.970 0.000 13.250 4.000 ;
    END
  END plaintext[40]
  PIN plaintext[41]
    DIRECTION INPUT ;
    USE SIGNAL ;
    PORT
      LAYER met3 ;
        RECT 0.000 81.640 4.000 82.240 ;
    END
  END plaintext[41]
  PIN plaintext[42]
    DIRECTION INPUT ;
    USE SIGNAL ;
    PORT
      LAYER met3 ;
        RECT 346.000 170.040 350.000 170.640 ;
    END
  END plaintext[42]
  PIN plaintext[43]
    DIRECTION INPUT ;
    USE SIGNAL ;
    PORT
      LAYER met2 ;
        RECT 190.070 0.000 190.350 4.000 ;
    END
  END plaintext[43]
  PIN plaintext[44]
    DIRECTION INPUT ;
    USE SIGNAL ;
    PORT
      LAYER met2 ;
        RECT 254.470 346.000 254.750 350.000 ;
    END
  END plaintext[44]
  PIN plaintext[45]
    DIRECTION INPUT ;
    USE SIGNAL ;
    PORT
      LAYER met2 ;
        RECT 334.970 346.000 335.250 350.000 ;
    END
  END plaintext[45]
  PIN plaintext[46]
    DIRECTION INPUT ;
    USE SIGNAL ;
    PORT
      LAYER met2 ;
        RECT 38.730 346.000 39.010 350.000 ;
    END
  END plaintext[46]
  PIN plaintext[47]
    DIRECTION INPUT ;
    USE SIGNAL ;
    PORT
      LAYER met3 ;
        RECT 0.000 163.240 4.000 163.840 ;
    END
  END plaintext[47]
  PIN plaintext[48]
    DIRECTION INPUT ;
    USE SIGNAL ;
    PORT
      LAYER met3 ;
        RECT 346.000 197.240 350.000 197.840 ;
    END
  END plaintext[48]
  PIN plaintext[49]
    DIRECTION INPUT ;
    USE SIGNAL ;
    PORT
      LAYER met2 ;
        RECT 341.410 346.000 341.690 350.000 ;
    END
  END plaintext[49]
  PIN plaintext[4]
    DIRECTION INPUT ;
    USE SIGNAL ;
    PORT
      LAYER met3 ;
        RECT 0.000 227.840 4.000 228.440 ;
    END
  END plaintext[4]
  PIN plaintext[50]
    DIRECTION INPUT ;
    USE SIGNAL ;
    PORT
      LAYER met3 ;
        RECT 346.000 261.840 350.000 262.440 ;
    END
  END plaintext[50]
  PIN plaintext[51]
    DIRECTION INPUT ;
    USE SIGNAL ;
    PORT
      LAYER met3 ;
        RECT 346.000 102.040 350.000 102.640 ;
    END
  END plaintext[51]
  PIN plaintext[52]
    DIRECTION INPUT ;
    USE SIGNAL ;
    PORT
      LAYER met2 ;
        RECT 231.930 0.000 232.210 4.000 ;
    END
  END plaintext[52]
  PIN plaintext[53]
    DIRECTION INPUT ;
    USE SIGNAL ;
    PORT
      LAYER met2 ;
        RECT 302.770 346.000 303.050 350.000 ;
    END
  END plaintext[53]
  PIN plaintext[54]
    DIRECTION INPUT ;
    USE SIGNAL ;
    PORT
      LAYER met2 ;
        RECT 99.910 346.000 100.190 350.000 ;
    END
  END plaintext[54]
  PIN plaintext[55]
    DIRECTION INPUT ;
    USE SIGNAL ;
    PORT
      LAYER met2 ;
        RECT 106.350 0.000 106.630 4.000 ;
    END
  END plaintext[55]
  PIN plaintext[56]
    DIRECTION INPUT ;
    USE SIGNAL ;
    PORT
      LAYER met3 ;
        RECT 346.000 200.640 350.000 201.240 ;
    END
  END plaintext[56]
  PIN plaintext[57]
    DIRECTION INPUT ;
    USE SIGNAL ;
    PORT
      LAYER met2 ;
        RECT 277.010 0.000 277.290 4.000 ;
    END
  END plaintext[57]
  PIN plaintext[58]
    DIRECTION INPUT ;
    USE SIGNAL ;
    PORT
      LAYER met3 ;
        RECT 0.000 57.840 4.000 58.440 ;
    END
  END plaintext[58]
  PIN plaintext[59]
    DIRECTION INPUT ;
    USE SIGNAL ;
    PORT
      LAYER met3 ;
        RECT 0.000 200.640 4.000 201.240 ;
    END
  END plaintext[59]
  PIN plaintext[5]
    DIRECTION INPUT ;
    USE SIGNAL ;
    PORT
      LAYER met3 ;
        RECT 346.000 0.040 350.000 0.640 ;
    END
  END plaintext[5]
  PIN plaintext[60]
    DIRECTION INPUT ;
    USE SIGNAL ;
    PORT
      LAYER met2 ;
        RECT 51.610 0.000 51.890 4.000 ;
    END
  END plaintext[60]
  PIN plaintext[61]
    DIRECTION INPUT ;
    USE SIGNAL ;
    PORT
      LAYER met2 ;
        RECT 164.310 0.000 164.590 4.000 ;
    END
  END plaintext[61]
  PIN plaintext[62]
    DIRECTION INPUT ;
    USE SIGNAL ;
    PORT
      LAYER met3 ;
        RECT 346.000 142.840 350.000 143.440 ;
    END
  END plaintext[62]
  PIN plaintext[63]
    DIRECTION INPUT ;
    USE SIGNAL ;
    PORT
      LAYER met2 ;
        RECT 286.670 346.000 286.950 350.000 ;
    END
  END plaintext[63]
  PIN plaintext[64]
    DIRECTION INPUT ;
    USE SIGNAL ;
    PORT
      LAYER met3 ;
        RECT 346.000 306.040 350.000 306.640 ;
    END
  END plaintext[64]
  PIN plaintext[65]
    DIRECTION INPUT ;
    USE SIGNAL ;
    PORT
      LAYER met3 ;
        RECT 346.000 3.440 350.000 4.040 ;
    END
  END plaintext[65]
  PIN plaintext[66]
    DIRECTION INPUT ;
    USE SIGNAL ;
    PORT
      LAYER met2 ;
        RECT 25.850 0.000 26.130 4.000 ;
    END
  END plaintext[66]
  PIN plaintext[67]
    DIRECTION INPUT ;
    USE SIGNAL ;
    PORT
      LAYER met3 ;
        RECT 346.000 190.440 350.000 191.040 ;
    END
  END plaintext[67]
  PIN plaintext[68]
    DIRECTION INPUT ;
    USE SIGNAL ;
    PORT
      LAYER met2 ;
        RECT 6.530 0.000 6.810 4.000 ;
    END
  END plaintext[68]
  PIN plaintext[69]
    DIRECTION INPUT ;
    USE SIGNAL ;
    PORT
      LAYER met3 ;
        RECT 346.000 316.240 350.000 316.840 ;
    END
  END plaintext[69]
  PIN plaintext[6]
    DIRECTION INPUT ;
    USE SIGNAL ;
    PORT
      LAYER met2 ;
        RECT 270.570 346.000 270.850 350.000 ;
    END
  END plaintext[6]
  PIN plaintext[70]
    DIRECTION INPUT ;
    USE SIGNAL ;
    PORT
      LAYER met3 ;
        RECT 346.000 30.640 350.000 31.240 ;
    END
  END plaintext[70]
  PIN plaintext[71]
    DIRECTION INPUT ;
    USE SIGNAL ;
    PORT
      LAYER met2 ;
        RECT 260.910 346.000 261.190 350.000 ;
    END
  END plaintext[71]
  PIN plaintext[72]
    DIRECTION INPUT ;
    USE SIGNAL ;
    PORT
      LAYER met3 ;
        RECT 0.000 108.840 4.000 109.440 ;
    END
  END plaintext[72]
  PIN plaintext[73]
    DIRECTION INPUT ;
    USE SIGNAL ;
    PORT
      LAYER met3 ;
        RECT 0.000 119.040 4.000 119.640 ;
    END
  END plaintext[73]
  PIN plaintext[74]
    DIRECTION INPUT ;
    USE SIGNAL ;
    PORT
      LAYER met2 ;
        RECT 225.490 0.000 225.770 4.000 ;
    END
  END plaintext[74]
  PIN plaintext[75]
    DIRECTION INPUT ;
    USE SIGNAL ;
    PORT
      LAYER met2 ;
        RECT 0.090 0.000 0.370 4.000 ;
    END
  END plaintext[75]
  PIN plaintext[76]
    DIRECTION INPUT ;
    USE SIGNAL ;
    PORT
      LAYER met2 ;
        RECT 267.350 0.000 267.630 4.000 ;
    END
  END plaintext[76]
  PIN plaintext[77]
    DIRECTION INPUT ;
    USE SIGNAL ;
    PORT
      LAYER met3 ;
        RECT 0.000 176.840 4.000 177.440 ;
    END
  END plaintext[77]
  PIN plaintext[78]
    DIRECTION INPUT ;
    USE SIGNAL ;
    PORT
      LAYER met3 ;
        RECT 0.000 316.240 4.000 316.840 ;
    END
  END plaintext[78]
  PIN plaintext[79]
    DIRECTION INPUT ;
    USE SIGNAL ;
    PORT
      LAYER met2 ;
        RECT 106.350 346.000 106.630 350.000 ;
    END
  END plaintext[79]
  PIN plaintext[7]
    DIRECTION INPUT ;
    USE SIGNAL ;
    PORT
      LAYER met3 ;
        RECT 0.000 122.440 4.000 123.040 ;
    END
  END plaintext[7]
  PIN plaintext[80]
    DIRECTION INPUT ;
    USE SIGNAL ;
    PORT
      LAYER met2 ;
        RECT 70.930 0.000 71.210 4.000 ;
    END
  END plaintext[80]
  PIN plaintext[81]
    DIRECTION INPUT ;
    USE SIGNAL ;
    PORT
      LAYER met2 ;
        RECT 22.630 0.000 22.910 4.000 ;
    END
  END plaintext[81]
  PIN plaintext[82]
    DIRECTION INPUT ;
    USE SIGNAL ;
    PORT
      LAYER met2 ;
        RECT 190.070 346.000 190.350 350.000 ;
    END
  END plaintext[82]
  PIN plaintext[83]
    DIRECTION INPUT ;
    USE SIGNAL ;
    PORT
      LAYER met2 ;
        RECT 112.790 346.000 113.070 350.000 ;
    END
  END plaintext[83]
  PIN plaintext[84]
    DIRECTION INPUT ;
    USE SIGNAL ;
    PORT
      LAYER met2 ;
        RECT 183.630 0.000 183.910 4.000 ;
    END
  END plaintext[84]
  PIN plaintext[85]
    DIRECTION INPUT ;
    USE SIGNAL ;
    PORT
      LAYER met2 ;
        RECT 244.810 346.000 245.090 350.000 ;
    END
  END plaintext[85]
  PIN plaintext[86]
    DIRECTION INPUT ;
    USE SIGNAL ;
    PORT
      LAYER met3 ;
        RECT 346.000 88.440 350.000 89.040 ;
    END
  END plaintext[86]
  PIN plaintext[87]
    DIRECTION INPUT ;
    USE SIGNAL ;
    PORT
      LAYER met3 ;
        RECT 0.000 238.040 4.000 238.640 ;
    END
  END plaintext[87]
  PIN plaintext[88]
    DIRECTION INPUT ;
    USE SIGNAL ;
    PORT
      LAYER met3 ;
        RECT 346.000 265.240 350.000 265.840 ;
    END
  END plaintext[88]
  PIN plaintext[89]
    DIRECTION INPUT ;
    USE SIGNAL ;
    PORT
      LAYER met2 ;
        RECT 74.150 0.000 74.430 4.000 ;
    END
  END plaintext[89]
  PIN plaintext[8]
    DIRECTION INPUT ;
    USE SIGNAL ;
    PORT
      LAYER met2 ;
        RECT 128.890 0.000 129.170 4.000 ;
    END
  END plaintext[8]
  PIN plaintext[90]
    DIRECTION INPUT ;
    USE SIGNAL ;
    PORT
      LAYER met3 ;
        RECT 0.000 30.640 4.000 31.240 ;
    END
  END plaintext[90]
  PIN plaintext[91]
    DIRECTION INPUT ;
    USE SIGNAL ;
    PORT
      LAYER met3 ;
        RECT 346.000 255.040 350.000 255.640 ;
    END
  END plaintext[91]
  PIN plaintext[92]
    DIRECTION INPUT ;
    USE SIGNAL ;
    PORT
      LAYER met2 ;
        RECT 206.170 0.000 206.450 4.000 ;
    END
  END plaintext[92]
  PIN plaintext[93]
    DIRECTION INPUT ;
    USE SIGNAL ;
    PORT
      LAYER met2 ;
        RECT 231.930 346.000 232.210 350.000 ;
    END
  END plaintext[93]
  PIN plaintext[94]
    DIRECTION INPUT ;
    USE SIGNAL ;
    PORT
      LAYER met2 ;
        RECT 228.710 346.000 228.990 350.000 ;
    END
  END plaintext[94]
  PIN plaintext[95]
    DIRECTION INPUT ;
    USE SIGNAL ;
    PORT
      LAYER met3 ;
        RECT 0.000 333.240 4.000 333.840 ;
    END
  END plaintext[95]
  PIN plaintext[96]
    DIRECTION INPUT ;
    USE SIGNAL ;
    PORT
      LAYER met2 ;
        RECT 45.170 346.000 45.450 350.000 ;
    END
  END plaintext[96]
  PIN plaintext[97]
    DIRECTION INPUT ;
    USE SIGNAL ;
    PORT
      LAYER met2 ;
        RECT 244.810 0.000 245.090 4.000 ;
    END
  END plaintext[97]
  PIN plaintext[98]
    DIRECTION INPUT ;
    USE SIGNAL ;
    PORT
      LAYER met3 ;
        RECT 0.000 78.240 4.000 78.840 ;
    END
  END plaintext[98]
  PIN plaintext[99]
    DIRECTION INPUT ;
    USE SIGNAL ;
    PORT
      LAYER met3 ;
        RECT 0.000 295.840 4.000 296.440 ;
    END
  END plaintext[99]
  PIN plaintext[9]
    DIRECTION INPUT ;
    USE SIGNAL ;
    PORT
      LAYER met3 ;
        RECT 346.000 163.240 350.000 163.840 ;
    END
  END plaintext[9]
  OBS
      LAYER li1 ;
        RECT 5.520 10.795 344.080 337.365 ;
      LAYER met1 ;
        RECT 0.070 10.640 348.150 337.520 ;
      LAYER met2 ;
        RECT 0.650 345.720 3.030 346.530 ;
        RECT 3.870 345.720 6.250 346.530 ;
        RECT 7.090 345.720 12.690 346.530 ;
        RECT 13.530 345.720 15.910 346.530 ;
        RECT 16.750 345.720 19.130 346.530 ;
        RECT 19.970 345.720 22.350 346.530 ;
        RECT 23.190 345.720 25.570 346.530 ;
        RECT 26.410 345.720 28.790 346.530 ;
        RECT 29.630 345.720 32.010 346.530 ;
        RECT 32.850 345.720 35.230 346.530 ;
        RECT 36.070 345.720 38.450 346.530 ;
        RECT 39.290 345.720 44.890 346.530 ;
        RECT 45.730 345.720 48.110 346.530 ;
        RECT 48.950 345.720 51.330 346.530 ;
        RECT 52.170 345.720 54.550 346.530 ;
        RECT 55.390 345.720 57.770 346.530 ;
        RECT 58.610 345.720 60.990 346.530 ;
        RECT 61.830 345.720 64.210 346.530 ;
        RECT 65.050 345.720 67.430 346.530 ;
        RECT 68.270 345.720 70.650 346.530 ;
        RECT 71.490 345.720 73.870 346.530 ;
        RECT 74.710 345.720 80.310 346.530 ;
        RECT 81.150 345.720 83.530 346.530 ;
        RECT 84.370 345.720 86.750 346.530 ;
        RECT 87.590 345.720 89.970 346.530 ;
        RECT 90.810 345.720 93.190 346.530 ;
        RECT 94.030 345.720 96.410 346.530 ;
        RECT 97.250 345.720 99.630 346.530 ;
        RECT 100.470 345.720 102.850 346.530 ;
        RECT 103.690 345.720 106.070 346.530 ;
        RECT 106.910 345.720 112.510 346.530 ;
        RECT 113.350 345.720 115.730 346.530 ;
        RECT 116.570 345.720 118.950 346.530 ;
        RECT 119.790 345.720 122.170 346.530 ;
        RECT 123.010 345.720 125.390 346.530 ;
        RECT 126.230 345.720 128.610 346.530 ;
        RECT 129.450 345.720 131.830 346.530 ;
        RECT 132.670 345.720 135.050 346.530 ;
        RECT 135.890 345.720 138.270 346.530 ;
        RECT 139.110 345.720 141.490 346.530 ;
        RECT 142.330 345.720 147.930 346.530 ;
        RECT 148.770 345.720 151.150 346.530 ;
        RECT 151.990 345.720 154.370 346.530 ;
        RECT 155.210 345.720 157.590 346.530 ;
        RECT 158.430 345.720 160.810 346.530 ;
        RECT 161.650 345.720 164.030 346.530 ;
        RECT 164.870 345.720 167.250 346.530 ;
        RECT 168.090 345.720 170.470 346.530 ;
        RECT 171.310 345.720 173.690 346.530 ;
        RECT 174.530 345.720 176.910 346.530 ;
        RECT 177.750 345.720 183.350 346.530 ;
        RECT 184.190 345.720 186.570 346.530 ;
        RECT 187.410 345.720 189.790 346.530 ;
        RECT 190.630 345.720 193.010 346.530 ;
        RECT 193.850 345.720 196.230 346.530 ;
        RECT 197.070 345.720 199.450 346.530 ;
        RECT 200.290 345.720 202.670 346.530 ;
        RECT 203.510 345.720 205.890 346.530 ;
        RECT 206.730 345.720 209.110 346.530 ;
        RECT 209.950 345.720 215.550 346.530 ;
        RECT 216.390 345.720 218.770 346.530 ;
        RECT 219.610 345.720 221.990 346.530 ;
        RECT 222.830 345.720 225.210 346.530 ;
        RECT 226.050 345.720 228.430 346.530 ;
        RECT 229.270 345.720 231.650 346.530 ;
        RECT 232.490 345.720 234.870 346.530 ;
        RECT 235.710 345.720 238.090 346.530 ;
        RECT 238.930 345.720 241.310 346.530 ;
        RECT 242.150 345.720 244.530 346.530 ;
        RECT 245.370 345.720 250.970 346.530 ;
        RECT 251.810 345.720 254.190 346.530 ;
        RECT 255.030 345.720 257.410 346.530 ;
        RECT 258.250 345.720 260.630 346.530 ;
        RECT 261.470 345.720 263.850 346.530 ;
        RECT 264.690 345.720 267.070 346.530 ;
        RECT 267.910 345.720 270.290 346.530 ;
        RECT 271.130 345.720 273.510 346.530 ;
        RECT 274.350 345.720 276.730 346.530 ;
        RECT 277.570 345.720 283.170 346.530 ;
        RECT 284.010 345.720 286.390 346.530 ;
        RECT 287.230 345.720 289.610 346.530 ;
        RECT 290.450 345.720 292.830 346.530 ;
        RECT 293.670 345.720 296.050 346.530 ;
        RECT 296.890 345.720 299.270 346.530 ;
        RECT 300.110 345.720 302.490 346.530 ;
        RECT 303.330 345.720 305.710 346.530 ;
        RECT 306.550 345.720 308.930 346.530 ;
        RECT 309.770 345.720 312.150 346.530 ;
        RECT 312.990 345.720 318.590 346.530 ;
        RECT 319.430 345.720 321.810 346.530 ;
        RECT 322.650 345.720 325.030 346.530 ;
        RECT 325.870 345.720 328.250 346.530 ;
        RECT 329.090 345.720 331.470 346.530 ;
        RECT 332.310 345.720 334.690 346.530 ;
        RECT 335.530 345.720 337.910 346.530 ;
        RECT 338.750 345.720 341.130 346.530 ;
        RECT 341.970 345.720 344.350 346.530 ;
        RECT 345.190 345.720 347.570 346.530 ;
        RECT 0.100 4.280 348.120 345.720 ;
        RECT 0.650 3.555 3.030 4.280 ;
        RECT 3.870 3.555 6.250 4.280 ;
        RECT 7.090 3.555 9.470 4.280 ;
        RECT 10.310 3.555 12.690 4.280 ;
        RECT 13.530 3.555 15.910 4.280 ;
        RECT 16.750 3.555 19.130 4.280 ;
        RECT 19.970 3.555 22.350 4.280 ;
        RECT 23.190 3.555 25.570 4.280 ;
        RECT 26.410 3.555 28.790 4.280 ;
        RECT 29.630 3.555 35.230 4.280 ;
        RECT 36.070 3.555 38.450 4.280 ;
        RECT 39.290 3.555 41.670 4.280 ;
        RECT 42.510 3.555 44.890 4.280 ;
        RECT 45.730 3.555 48.110 4.280 ;
        RECT 48.950 3.555 51.330 4.280 ;
        RECT 52.170 3.555 54.550 4.280 ;
        RECT 55.390 3.555 57.770 4.280 ;
        RECT 58.610 3.555 60.990 4.280 ;
        RECT 61.830 3.555 64.210 4.280 ;
        RECT 65.050 3.555 70.650 4.280 ;
        RECT 71.490 3.555 73.870 4.280 ;
        RECT 74.710 3.555 77.090 4.280 ;
        RECT 77.930 3.555 80.310 4.280 ;
        RECT 81.150 3.555 83.530 4.280 ;
        RECT 84.370 3.555 86.750 4.280 ;
        RECT 87.590 3.555 89.970 4.280 ;
        RECT 90.810 3.555 93.190 4.280 ;
        RECT 94.030 3.555 96.410 4.280 ;
        RECT 97.250 3.555 102.850 4.280 ;
        RECT 103.690 3.555 106.070 4.280 ;
        RECT 106.910 3.555 109.290 4.280 ;
        RECT 110.130 3.555 112.510 4.280 ;
        RECT 113.350 3.555 115.730 4.280 ;
        RECT 116.570 3.555 118.950 4.280 ;
        RECT 119.790 3.555 122.170 4.280 ;
        RECT 123.010 3.555 125.390 4.280 ;
        RECT 126.230 3.555 128.610 4.280 ;
        RECT 129.450 3.555 131.830 4.280 ;
        RECT 132.670 3.555 138.270 4.280 ;
        RECT 139.110 3.555 141.490 4.280 ;
        RECT 142.330 3.555 144.710 4.280 ;
        RECT 145.550 3.555 147.930 4.280 ;
        RECT 148.770 3.555 151.150 4.280 ;
        RECT 151.990 3.555 154.370 4.280 ;
        RECT 155.210 3.555 157.590 4.280 ;
        RECT 158.430 3.555 160.810 4.280 ;
        RECT 161.650 3.555 164.030 4.280 ;
        RECT 164.870 3.555 170.470 4.280 ;
        RECT 171.310 3.555 173.690 4.280 ;
        RECT 174.530 3.555 176.910 4.280 ;
        RECT 177.750 3.555 180.130 4.280 ;
        RECT 180.970 3.555 183.350 4.280 ;
        RECT 184.190 3.555 186.570 4.280 ;
        RECT 187.410 3.555 189.790 4.280 ;
        RECT 190.630 3.555 193.010 4.280 ;
        RECT 193.850 3.555 196.230 4.280 ;
        RECT 197.070 3.555 199.450 4.280 ;
        RECT 200.290 3.555 205.890 4.280 ;
        RECT 206.730 3.555 209.110 4.280 ;
        RECT 209.950 3.555 212.330 4.280 ;
        RECT 213.170 3.555 215.550 4.280 ;
        RECT 216.390 3.555 218.770 4.280 ;
        RECT 219.610 3.555 221.990 4.280 ;
        RECT 222.830 3.555 225.210 4.280 ;
        RECT 226.050 3.555 228.430 4.280 ;
        RECT 229.270 3.555 231.650 4.280 ;
        RECT 232.490 3.555 234.870 4.280 ;
        RECT 235.710 3.555 241.310 4.280 ;
        RECT 242.150 3.555 244.530 4.280 ;
        RECT 245.370 3.555 247.750 4.280 ;
        RECT 248.590 3.555 250.970 4.280 ;
        RECT 251.810 3.555 254.190 4.280 ;
        RECT 255.030 3.555 257.410 4.280 ;
        RECT 258.250 3.555 260.630 4.280 ;
        RECT 261.470 3.555 263.850 4.280 ;
        RECT 264.690 3.555 267.070 4.280 ;
        RECT 267.910 3.555 273.510 4.280 ;
        RECT 274.350 3.555 276.730 4.280 ;
        RECT 277.570 3.555 279.950 4.280 ;
        RECT 280.790 3.555 283.170 4.280 ;
        RECT 284.010 3.555 286.390 4.280 ;
        RECT 287.230 3.555 289.610 4.280 ;
        RECT 290.450 3.555 292.830 4.280 ;
        RECT 293.670 3.555 296.050 4.280 ;
        RECT 296.890 3.555 299.270 4.280 ;
        RECT 300.110 3.555 302.490 4.280 ;
        RECT 303.330 3.555 308.930 4.280 ;
        RECT 309.770 3.555 312.150 4.280 ;
        RECT 312.990 3.555 315.370 4.280 ;
        RECT 316.210 3.555 318.590 4.280 ;
        RECT 319.430 3.555 321.810 4.280 ;
        RECT 322.650 3.555 325.030 4.280 ;
        RECT 325.870 3.555 328.250 4.280 ;
        RECT 329.090 3.555 331.470 4.280 ;
        RECT 332.310 3.555 334.690 4.280 ;
        RECT 335.530 3.555 341.130 4.280 ;
        RECT 341.970 3.555 344.350 4.280 ;
        RECT 345.190 3.555 347.570 4.280 ;
      LAYER met3 ;
        RECT 4.400 343.040 345.600 343.905 ;
        RECT 3.990 341.040 346.000 343.040 ;
        RECT 4.400 339.640 345.600 341.040 ;
        RECT 3.990 337.640 346.000 339.640 ;
        RECT 4.400 336.240 345.600 337.640 ;
        RECT 3.990 334.240 346.000 336.240 ;
        RECT 4.400 332.840 345.600 334.240 ;
        RECT 3.990 330.840 346.000 332.840 ;
        RECT 4.400 329.440 345.600 330.840 ;
        RECT 3.990 327.440 346.000 329.440 ;
        RECT 4.400 326.040 345.600 327.440 ;
        RECT 3.990 324.040 346.000 326.040 ;
        RECT 3.990 322.640 345.600 324.040 ;
        RECT 3.990 320.640 346.000 322.640 ;
        RECT 4.400 319.240 345.600 320.640 ;
        RECT 3.990 317.240 346.000 319.240 ;
        RECT 4.400 315.840 345.600 317.240 ;
        RECT 3.990 313.840 346.000 315.840 ;
        RECT 4.400 312.440 346.000 313.840 ;
        RECT 3.990 310.440 346.000 312.440 ;
        RECT 4.400 309.040 345.600 310.440 ;
        RECT 3.990 307.040 346.000 309.040 ;
        RECT 4.400 305.640 345.600 307.040 ;
        RECT 3.990 303.640 346.000 305.640 ;
        RECT 4.400 302.240 345.600 303.640 ;
        RECT 3.990 300.240 346.000 302.240 ;
        RECT 4.400 298.840 345.600 300.240 ;
        RECT 3.990 296.840 346.000 298.840 ;
        RECT 4.400 295.440 345.600 296.840 ;
        RECT 3.990 293.440 346.000 295.440 ;
        RECT 4.400 292.040 345.600 293.440 ;
        RECT 3.990 290.040 346.000 292.040 ;
        RECT 4.400 288.640 345.600 290.040 ;
        RECT 3.990 286.640 346.000 288.640 ;
        RECT 3.990 285.240 345.600 286.640 ;
        RECT 3.990 283.240 346.000 285.240 ;
        RECT 4.400 281.840 345.600 283.240 ;
        RECT 3.990 279.840 346.000 281.840 ;
        RECT 4.400 278.440 345.600 279.840 ;
        RECT 3.990 276.440 346.000 278.440 ;
        RECT 4.400 275.040 346.000 276.440 ;
        RECT 3.990 273.040 346.000 275.040 ;
        RECT 4.400 271.640 345.600 273.040 ;
        RECT 3.990 269.640 346.000 271.640 ;
        RECT 4.400 268.240 345.600 269.640 ;
        RECT 3.990 266.240 346.000 268.240 ;
        RECT 4.400 264.840 345.600 266.240 ;
        RECT 3.990 262.840 346.000 264.840 ;
        RECT 4.400 261.440 345.600 262.840 ;
        RECT 3.990 259.440 346.000 261.440 ;
        RECT 4.400 258.040 345.600 259.440 ;
        RECT 3.990 256.040 346.000 258.040 ;
        RECT 4.400 254.640 345.600 256.040 ;
        RECT 3.990 252.640 346.000 254.640 ;
        RECT 3.990 251.240 345.600 252.640 ;
        RECT 3.990 249.240 346.000 251.240 ;
        RECT 4.400 247.840 345.600 249.240 ;
        RECT 3.990 245.840 346.000 247.840 ;
        RECT 4.400 244.440 345.600 245.840 ;
        RECT 3.990 242.440 346.000 244.440 ;
        RECT 4.400 241.040 346.000 242.440 ;
        RECT 3.990 239.040 346.000 241.040 ;
        RECT 4.400 237.640 345.600 239.040 ;
        RECT 3.990 235.640 346.000 237.640 ;
        RECT 4.400 234.240 345.600 235.640 ;
        RECT 3.990 232.240 346.000 234.240 ;
        RECT 4.400 230.840 345.600 232.240 ;
        RECT 3.990 228.840 346.000 230.840 ;
        RECT 4.400 227.440 345.600 228.840 ;
        RECT 3.990 225.440 346.000 227.440 ;
        RECT 4.400 224.040 345.600 225.440 ;
        RECT 3.990 222.040 346.000 224.040 ;
        RECT 4.400 220.640 345.600 222.040 ;
        RECT 3.990 218.640 346.000 220.640 ;
        RECT 4.400 217.240 345.600 218.640 ;
        RECT 3.990 215.240 346.000 217.240 ;
        RECT 3.990 213.840 345.600 215.240 ;
        RECT 3.990 211.840 346.000 213.840 ;
        RECT 4.400 210.440 345.600 211.840 ;
        RECT 3.990 208.440 346.000 210.440 ;
        RECT 4.400 207.040 345.600 208.440 ;
        RECT 3.990 205.040 346.000 207.040 ;
        RECT 4.400 203.640 346.000 205.040 ;
        RECT 3.990 201.640 346.000 203.640 ;
        RECT 4.400 200.240 345.600 201.640 ;
        RECT 3.990 198.240 346.000 200.240 ;
        RECT 4.400 196.840 345.600 198.240 ;
        RECT 3.990 194.840 346.000 196.840 ;
        RECT 4.400 193.440 345.600 194.840 ;
        RECT 3.990 191.440 346.000 193.440 ;
        RECT 4.400 190.040 345.600 191.440 ;
        RECT 3.990 188.040 346.000 190.040 ;
        RECT 4.400 186.640 345.600 188.040 ;
        RECT 3.990 184.640 346.000 186.640 ;
        RECT 4.400 183.240 345.600 184.640 ;
        RECT 3.990 181.240 346.000 183.240 ;
        RECT 3.990 179.840 345.600 181.240 ;
        RECT 3.990 177.840 346.000 179.840 ;
        RECT 4.400 176.440 345.600 177.840 ;
        RECT 3.990 174.440 346.000 176.440 ;
        RECT 4.400 173.040 345.600 174.440 ;
        RECT 3.990 171.040 346.000 173.040 ;
        RECT 4.400 169.640 345.600 171.040 ;
        RECT 3.990 167.640 346.000 169.640 ;
        RECT 4.400 166.240 346.000 167.640 ;
        RECT 3.990 164.240 346.000 166.240 ;
        RECT 4.400 162.840 345.600 164.240 ;
        RECT 3.990 160.840 346.000 162.840 ;
        RECT 4.400 159.440 345.600 160.840 ;
        RECT 3.990 157.440 346.000 159.440 ;
        RECT 4.400 156.040 345.600 157.440 ;
        RECT 3.990 154.040 346.000 156.040 ;
        RECT 4.400 152.640 345.600 154.040 ;
        RECT 3.990 150.640 346.000 152.640 ;
        RECT 4.400 149.240 345.600 150.640 ;
        RECT 3.990 147.240 346.000 149.240 ;
        RECT 4.400 145.840 345.600 147.240 ;
        RECT 3.990 143.840 346.000 145.840 ;
        RECT 3.990 142.440 345.600 143.840 ;
        RECT 3.990 140.440 346.000 142.440 ;
        RECT 4.400 139.040 345.600 140.440 ;
        RECT 3.990 137.040 346.000 139.040 ;
        RECT 4.400 135.640 345.600 137.040 ;
        RECT 3.990 133.640 346.000 135.640 ;
        RECT 4.400 132.240 346.000 133.640 ;
        RECT 3.990 130.240 346.000 132.240 ;
        RECT 4.400 128.840 345.600 130.240 ;
        RECT 3.990 126.840 346.000 128.840 ;
        RECT 4.400 125.440 345.600 126.840 ;
        RECT 3.990 123.440 346.000 125.440 ;
        RECT 4.400 122.040 345.600 123.440 ;
        RECT 3.990 120.040 346.000 122.040 ;
        RECT 4.400 118.640 345.600 120.040 ;
        RECT 3.990 116.640 346.000 118.640 ;
        RECT 4.400 115.240 345.600 116.640 ;
        RECT 3.990 113.240 346.000 115.240 ;
        RECT 4.400 111.840 345.600 113.240 ;
        RECT 3.990 109.840 346.000 111.840 ;
        RECT 4.400 108.440 345.600 109.840 ;
        RECT 3.990 106.440 346.000 108.440 ;
        RECT 3.990 105.040 345.600 106.440 ;
        RECT 3.990 103.040 346.000 105.040 ;
        RECT 4.400 101.640 345.600 103.040 ;
        RECT 3.990 99.640 346.000 101.640 ;
        RECT 4.400 98.240 345.600 99.640 ;
        RECT 3.990 96.240 346.000 98.240 ;
        RECT 4.400 94.840 346.000 96.240 ;
        RECT 3.990 92.840 346.000 94.840 ;
        RECT 4.400 91.440 345.600 92.840 ;
        RECT 3.990 89.440 346.000 91.440 ;
        RECT 4.400 88.040 345.600 89.440 ;
        RECT 3.990 86.040 346.000 88.040 ;
        RECT 4.400 84.640 345.600 86.040 ;
        RECT 3.990 82.640 346.000 84.640 ;
        RECT 4.400 81.240 345.600 82.640 ;
        RECT 3.990 79.240 346.000 81.240 ;
        RECT 4.400 77.840 345.600 79.240 ;
        RECT 3.990 75.840 346.000 77.840 ;
        RECT 4.400 74.440 345.600 75.840 ;
        RECT 3.990 72.440 346.000 74.440 ;
        RECT 3.990 71.040 345.600 72.440 ;
        RECT 3.990 69.040 346.000 71.040 ;
        RECT 4.400 67.640 345.600 69.040 ;
        RECT 3.990 65.640 346.000 67.640 ;
        RECT 4.400 64.240 345.600 65.640 ;
        RECT 3.990 62.240 346.000 64.240 ;
        RECT 4.400 60.840 346.000 62.240 ;
        RECT 3.990 58.840 346.000 60.840 ;
        RECT 4.400 57.440 345.600 58.840 ;
        RECT 3.990 55.440 346.000 57.440 ;
        RECT 4.400 54.040 345.600 55.440 ;
        RECT 3.990 52.040 346.000 54.040 ;
        RECT 4.400 50.640 345.600 52.040 ;
        RECT 3.990 48.640 346.000 50.640 ;
        RECT 4.400 47.240 345.600 48.640 ;
        RECT 3.990 45.240 346.000 47.240 ;
        RECT 4.400 43.840 345.600 45.240 ;
        RECT 3.990 41.840 346.000 43.840 ;
        RECT 4.400 40.440 345.600 41.840 ;
        RECT 3.990 38.440 346.000 40.440 ;
        RECT 4.400 37.040 345.600 38.440 ;
        RECT 3.990 35.040 346.000 37.040 ;
        RECT 3.990 33.640 345.600 35.040 ;
        RECT 3.990 31.640 346.000 33.640 ;
        RECT 4.400 30.240 345.600 31.640 ;
        RECT 3.990 28.240 346.000 30.240 ;
        RECT 4.400 26.840 345.600 28.240 ;
        RECT 3.990 24.840 346.000 26.840 ;
        RECT 4.400 23.440 346.000 24.840 ;
        RECT 3.990 21.440 346.000 23.440 ;
        RECT 4.400 20.040 345.600 21.440 ;
        RECT 3.990 18.040 346.000 20.040 ;
        RECT 4.400 16.640 345.600 18.040 ;
        RECT 3.990 14.640 346.000 16.640 ;
        RECT 4.400 13.240 345.600 14.640 ;
        RECT 3.990 11.240 346.000 13.240 ;
        RECT 4.400 9.840 345.600 11.240 ;
        RECT 3.990 7.840 346.000 9.840 ;
        RECT 4.400 6.440 345.600 7.840 ;
        RECT 3.990 4.440 346.000 6.440 ;
        RECT 4.400 3.575 345.600 4.440 ;
  END
END aes_top
END LIBRARY

